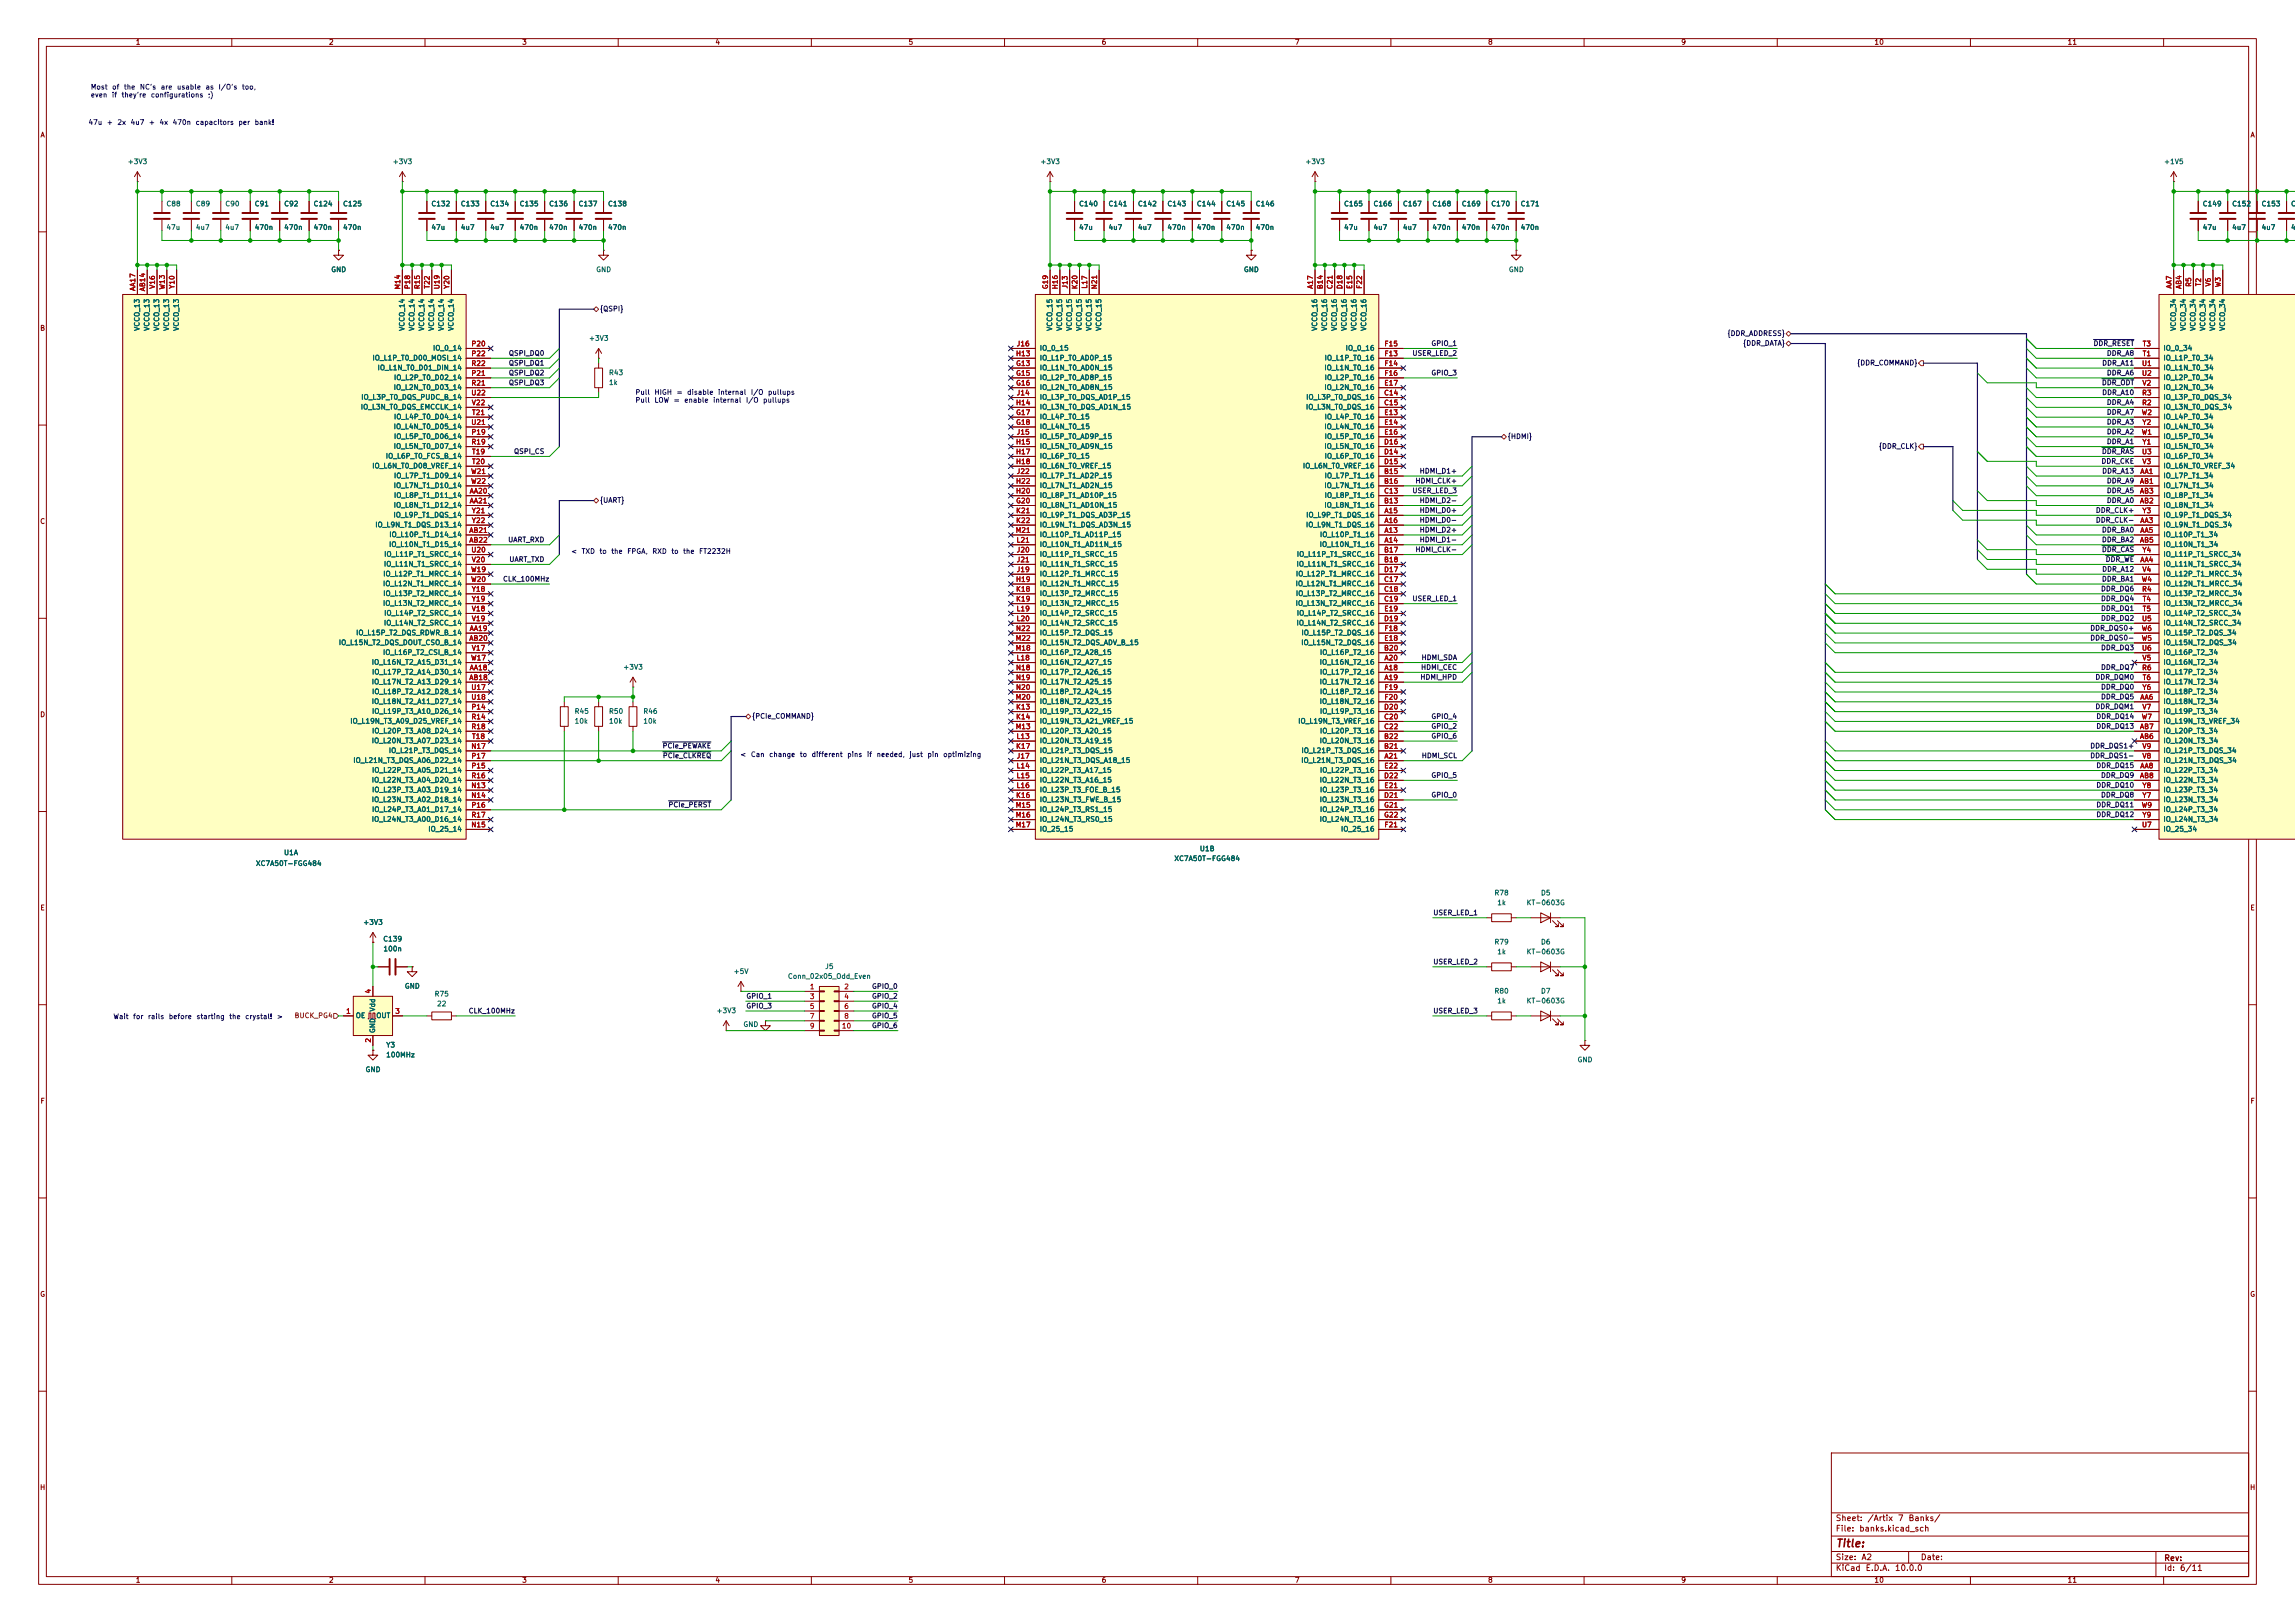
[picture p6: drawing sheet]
<svg xmlns="http://www.w3.org/2000/svg" width="594mm" height="420mm" viewBox="0 0 594 420" stroke-linecap="round" stroke-linejoin="round" font-family="sans-serif">
<defs><g id="words">
<text font-size="2" fill="#840000" x="475" y="400.9">Title:</text>
<g font-size="1.5" fill="#840000">
<text x="475" y="394">Sheet:</text>
<text x="483.2" y="394">/Artix</text>
<text x="491.1" y="394">7</text>
<text x="493.8" y="394">Banks/</text>
<text x="475" y="396.7">File:</text>
<text x="481.1" y="396.7">banks.kicad_sch</text>
<text x="475" y="406.9">KiCad</text>
<text x="475" y="404.1">Size:</text>
<text x="481.7" y="404.1">A2</text>
<text x="482.7" y="406.9">E.D.A.</text>
<text x="490.3" y="406.9">10.0.0</text>
<text x="497" y="404.1">Date:</text>
<text x="560" y="404.3">Rev:</text>
<text x="560" y="406.9">Id:</text>
<text x="564.1" y="406.9">6/11</text>
</g>
<g font-size="1.3" fill="#840000">
<text x="35" y="11.9">1</text>
<text x="85" y="11.9">2</text>
<text x="135" y="11.9">3</text>
<text x="185" y="11.9">4</text>
<text x="235" y="11.9">5</text>
<text x="285" y="11.9">6</text>
<text x="335" y="11.9">7</text>
<text x="385" y="11.9">8</text>
<text x="435" y="11.9">9</text>
<text x="485" y="11.9">10</text>
<text x="535" y="11.9">11</text>
<text x="10.3" y="35.9">A</text>
<text x="582.3" y="35.9">A</text>
<text x="10.3" y="85.9">B</text>
<text x="10.3" y="135.9">C</text>
<text x="10.3" y="185.9">D</text>
<text x="10.3" y="235.9">E</text>
<text x="582.3" y="235.9">E</text>
<text x="10.3" y="285.9">F</text>
<text x="582.3" y="285.9">F</text>
<text x="10.3" y="335.9">G</text>
<text x="582.3" y="335.9">G</text>
<text x="10.2" y="385.9">H</text>
<text x="582.2" y="385.9">H</text>
<text x="35" y="409.9">1</text>
<text x="85" y="409.9">2</text>
<text x="135" y="409.9">3</text>
<text x="185" y="409.9">4</text>
<text x="235" y="409.9">5</text>
<text x="285" y="409.9">6</text>
<text x="335" y="409.9">7</text>
<text x="385" y="409.9">8</text>
<text x="435" y="409.9">9</text>
<text x="485" y="409.9">10</text>
<text x="535" y="409.9">11</text>
</g>
<g font-size="1.3" fill="#0000c2">
<text x="23.4" y="23.5">Most</text>
<text x="28.9" y="23.5">of</text>
<text x="31.9" y="23.5">the</text>
<text x="36.1" y="23.5">NC's</text>
<text x="41.5" y="23.5">are</text>
<text x="45.7" y="23.5">usable</text>
<text x="53.1" y="23.5">as</text>
<text x="56.4" y="23.5">I/O's</text>
<text x="62.5" y="23.5">too,</text>
<text x="23.4" y="25.5">even</text>
<text x="28.8" y="25.5">if</text>
<text x="31.3" y="25.5">they're</text>
<text x="38.9" y="25.5">configurations</text>
<text x="53.7" y="25.5">;)</text>
<text x="22.8" y="32.6">47u</text>
<text x="27.5" y="32.6">+</text>
<text x="30.2" y="32.6">2x</text>
<text x="33.7" y="32.6">4u7</text>
<text x="38.4" y="32.6">+</text>
<text x="41.1" y="32.6">4x</text>
<text x="44.5" y="32.6">470n</text>
<text x="50.5" y="32.6">capacitors</text>
<text x="61.6" y="32.6">per</text>
<text x="65.8" y="32.6">bank!</text>
<text x="164.3" y="102.5">Pull</text>
<text x="164.3" y="104.5">Pull</text>
<text x="169.3" y="102.5">HIGH</text>
<text x="169.3" y="104.5">LOW</text>
<text x="174.2" y="104.5">=</text>
<text x="175" y="102.5">=</text>
<text x="177" y="104.5">enable</text>
<text x="177.7" y="102.5">disable</text>
<text x="184.4" y="104.5">internal</text>
<text x="185.7" y="102.5">internal</text>
<text x="192.9" y="104.5">I/O</text>
<text x="194.2" y="102.5">I/O</text>
<text x="197.4" y="104.5">pullups</text>
<text x="198.6" y="102.5">pullups</text>
<text x="147.7" y="143.6">&lt;</text>
<text x="150.4" y="143.6">TXD</text>
<text x="155" y="143.6">to</text>
<text x="158.1" y="143.6">the</text>
<text x="162.2" y="143.6">FPGA,</text>
<text x="168.7" y="143.6">RXD</text>
<text x="173.6" y="143.6">to</text>
<text x="176.7" y="143.6">the</text>
<text x="180.8" y="143.6">FT2232H</text>
<text x="191.5" y="196.2">&lt;</text>
<text x="194.2" y="196.2">Can</text>
<text x="198.9" y="196.2">change</text>
<text x="206.9" y="196.2">to</text>
<text x="209.9" y="196.2">different</text>
<text x="219.1" y="196.2">pins</text>
<text x="224.3" y="196.2">if</text>
<text x="226.8" y="196.2">needed,</text>
<text x="235.2" y="196.2">just</text>
<text x="239.9" y="196.2">pin</text>
<text x="244" y="196.2">optimizing</text>
<text x="29.2" y="264">Wait</text>
<text x="34.3" y="264">for</text>
<text x="38.2" y="264">rails</text>
<text x="43.6" y="264">before</text>
<text x="50.7" y="264">starting</text>
<text x="59.2" y="264">the</text>
<text x="63.3" y="264">crystal!</text>
<text x="71.5" y="264">&gt;</text>
</g>
<g font-size="1.3" fill="#006464">
<text x="32.9" y="42.8">+3V3</text>
<text x="101.5" y="42.8">+3V3</text>
<text x="269.1" y="42.8">+3V3</text>
<text x="337.7" y="42.8">+3V3</text>
<text x="560" y="42.8">+1V5</text>
<text x="42.9" y="53.7">C88</text>
<text x="50.6" y="53.7">C89</text>
<text x="58.2" y="53.7">C90</text>
<text x="65.8" y="53.7">C91</text>
<text x="73.4" y="53.7">C92</text>
<text x="81" y="53.7">C124</text>
<text x="88.7" y="53.7">C125</text>
<text x="111.5" y="53.7">C132</text>
<text x="119.1" y="53.7">C133</text>
<text x="126.8" y="53.7">C134</text>
<text x="134.4" y="53.7">C135</text>
<text x="142" y="53.7">C136</text>
<text x="149.6" y="53.7">C137</text>
<text x="157.2" y="53.7">C138</text>
<text x="279.2" y="53.7">C140</text>
<text x="286.8" y="53.7">C141</text>
<text x="294.4" y="53.7">C142</text>
<text x="302" y="53.7">C143</text>
<text x="309.6" y="53.7">C144</text>
<text x="317.3" y="53.7">C145</text>
<text x="324.9" y="53.7">C146</text>
<text x="347.7" y="53.7">C165</text>
<text x="355.4" y="53.7">C166</text>
<text x="363" y="53.7">C167</text>
<text x="370.6" y="53.7">C168</text>
<text x="378.2" y="53.7">C169</text>
<text x="385.8" y="53.7">C170</text>
<text x="393.5" y="53.7">C171</text>
<text x="570" y="53.7">C149</text>
<text x="577.6" y="53.7">C152</text>
<text x="585.2" y="53.7">C153</text>
<text x="592.8" y="53.7">C1</text>
<text x="42.9" y="59.8">47u</text>
<text x="50.6" y="59.8">4u7</text>
<text x="58.2" y="59.8">4u7</text>
<text x="65.8" y="59.8">470n</text>
<text x="73.4" y="59.8">470n</text>
<text x="81" y="59.8">470n</text>
<text x="88.7" y="59.8">470n</text>
<text x="111.5" y="59.8">47u</text>
<text x="119.1" y="59.8">4u7</text>
<text x="126.8" y="59.8">4u7</text>
<text x="134.4" y="59.8">470n</text>
<text x="142" y="59.8">470n</text>
<text x="149.6" y="59.8">470n</text>
<text x="157.2" y="59.8">470n</text>
<text x="279.2" y="59.8">47u</text>
<text x="286.8" y="59.8">4u7</text>
<text x="294.4" y="59.8">4u7</text>
<text x="302" y="59.8">470n</text>
<text x="309.6" y="59.8">470n</text>
<text x="317.3" y="59.8">470n</text>
<text x="324.9" y="59.8">470n</text>
<text x="347.7" y="59.8">47u</text>
<text x="355.4" y="59.8">4u7</text>
<text x="363" y="59.8">4u7</text>
<text x="370.6" y="59.8">470n</text>
<text x="378.2" y="59.8">470n</text>
<text x="385.8" y="59.8">470n</text>
<text x="393.5" y="59.8">470n</text>
<text x="570" y="59.8">47u</text>
<text x="577.6" y="59.8">4u7</text>
<text x="585.2" y="59.8">4u7</text>
<text x="592.8" y="59.8">47</text>
<text x="85.6" y="70.7">GND</text>
<text x="154.2" y="70.7">GND</text>
<text x="321.8" y="70.7">GND</text>
<text x="390.4" y="70.7">GND</text>
<text x="36.4" y="85.8" transform="rotate(-90 36.4 85.8)">VCCO_13</text>
<text x="39" y="85.8" transform="rotate(-90 39 85.8)">VCCO_13</text>
<text x="41.5" y="85.8" transform="rotate(-90 41.5 85.8)">VCCO_13</text>
<text x="44" y="85.8" transform="rotate(-90 44 85.8)">VCCO_13</text>
<text x="46.6" y="85.8" transform="rotate(-90 46.6 85.8)">VCCO_13</text>
<text x="105" y="85.8" transform="rotate(-90 105 85.8)">VCCO_14</text>
<text x="107.5" y="85.8" transform="rotate(-90 107.5 85.8)">VCCO_14</text>
<text x="110.1" y="85.8" transform="rotate(-90 110.1 85.8)">VCCO_14</text>
<text x="112.6" y="85.8" transform="rotate(-90 112.6 85.8)">VCCO_14</text>
<text x="115.2" y="85.8" transform="rotate(-90 115.2 85.8)">VCCO_14</text>
<text x="117.7" y="85.8" transform="rotate(-90 117.7 85.8)">VCCO_14</text>
<text x="152.3" y="88.5">+3V3</text>
<text x="272.6" y="85.8" transform="rotate(-90 272.6 85.8)">VCCO_15</text>
<text x="275.2" y="85.8" transform="rotate(-90 275.2 85.8)">VCCO_15</text>
<text x="277.7" y="85.8" transform="rotate(-90 277.7 85.8)">VCCO_15</text>
<text x="280.3" y="85.8" transform="rotate(-90 280.3 85.8)">VCCO_15</text>
<text x="282.8" y="85.8" transform="rotate(-90 282.8 85.8)">VCCO_15</text>
<text x="285.3" y="85.8" transform="rotate(-90 285.3 85.8)">VCCO_15</text>
<text x="341.2" y="85.8" transform="rotate(-90 341.2 85.8)">VCCO_16</text>
<text x="343.8" y="85.8" transform="rotate(-90 343.8 85.8)">VCCO_16</text>
<text x="346.3" y="85.8" transform="rotate(-90 346.3 85.8)">VCCO_16</text>
<text x="348.8" y="85.8" transform="rotate(-90 348.8 85.8)">VCCO_16</text>
<text x="351.4" y="85.8" transform="rotate(-90 351.4 85.8)">VCCO_16</text>
<text x="353.9" y="85.8" transform="rotate(-90 353.9 85.8)">VCCO_16</text>
<text x="563.5" y="85.8" transform="rotate(-90 563.5 85.8)">VCCO_34</text>
<text x="566" y="85.8" transform="rotate(-90 566 85.8)">VCCO_34</text>
<text x="568.6" y="85.8" transform="rotate(-90 568.6 85.8)">VCCO_34</text>
<text x="571.1" y="85.8" transform="rotate(-90 571.1 85.8)">VCCO_34</text>
<text x="573.6" y="85.8" transform="rotate(-90 573.6 85.8)">VCCO_34</text>
<text x="576.2" y="85.8" transform="rotate(-90 576.2 85.8)">VCCO_34</text>
<text x="96.3" y="93.6">IO_L1P_T0_D00_MOSI_14</text>
<text x="111.9" y="91">IO_0_14</text>
<text x="269" y="93.6">IO_L1P_T0_AD0P_15</text>
<text x="269" y="91">IO_0_15</text>
<text x="342.7" y="93.6">IO_L1P_T0_16</text>
<text x="348.2" y="91">IO_0_16</text>
<text x="559.8" y="93.6">IO_L1P_T0_34</text>
<text x="559.8" y="91">IO_0_34</text>
<text x="97.6" y="96.1">IO_L1N_T0_D01_DIN_14</text>
<text x="101.8" y="101.2">IO_L2N_T0_D03_14</text>
<text x="101.8" y="98.7">IO_L2P_T0_D02_14</text>
<text x="157.5" y="97.4">R43</text>
<text x="157.5" y="99.9">1k</text>
<text x="269" y="96.1">IO_L1N_T0_AD0N_15</text>
<text x="269" y="98.7">IO_L2P_T0_AD8P_15</text>
<text x="269" y="101.2">IO_L2N_T0_AD8N_15</text>
<text x="342.6" y="101.2">IO_L2N_T0_16</text>
<text x="342.6" y="96.1">IO_L1N_T0_16</text>
<text x="342.7" y="98.7">IO_L2P_T0_16</text>
<text x="559.8" y="96.1">IO_L1N_T0_34</text>
<text x="559.8" y="98.7">IO_L2P_T0_34</text>
<text x="559.8" y="101.2">IO_L2N_T0_34</text>
<text x="93.2" y="106.3">IO_L3N_T0_DQS_EMCCLK_14</text>
<text x="93.4" y="103.7">IO_L3P_T0_DQS_PUDC_B_14</text>
<text x="269" y="106.3">IO_L3N_T0_DQS_AD1N_15</text>
<text x="269" y="103.7">IO_L3P_T0_DQS_AD1P_15</text>
<text x="337.9" y="106.3">IO_L3N_T0_DQS_16</text>
<text x="337.9" y="103.7">IO_L3P_T0_DQS_16</text>
<text x="559.8" y="106.3">IO_L3N_T0_DQS_34</text>
<text x="559.8" y="103.7">IO_L3P_T0_DQS_34</text>
<text x="101.8" y="111.4">IO_L4N_T0_D05_14</text>
<text x="101.8" y="113.9">IO_L5P_T0_D06_14</text>
<text x="101.8" y="108.8">IO_L4P_T0_D04_14</text>
<text x="269" y="108.8">IO_L4P_T0_15</text>
<text x="269" y="111.4">IO_L4N_T0_15</text>
<text x="269" y="113.9">IO_L5P_T0_AD9P_15</text>
<text x="342.6" y="111.4">IO_L4N_T0_16</text>
<text x="342.7" y="108.8">IO_L4P_T0_16</text>
<text x="342.7" y="113.9">IO_L5P_T0_16</text>
<text x="559.8" y="113.9">IO_L5P_T0_34</text>
<text x="559.8" y="108.8">IO_L4P_T0_34</text>
<text x="559.8" y="111.4">IO_L4N_T0_34</text>
<text x="99.7" y="119">IO_L6P_T0_FCS_B_14</text>
<text x="101.8" y="116.4">IO_L5N_T0_D07_14</text>
<text x="269" y="116.4">IO_L5N_T0_AD9N_15</text>
<text x="269" y="119">IO_L6P_T0_15</text>
<text x="342.6" y="116.4">IO_L5N_T0_16</text>
<text x="342.7" y="119">IO_L6P_T0_16</text>
<text x="559.8" y="119">IO_L6P_T0_34</text>
<text x="559.8" y="116.4">IO_L5N_T0_34</text>
<text x="96.2" y="121.5">IO_L6N_T0_D08_VREF_14</text>
<text x="101.8" y="124.1">IO_L7P_T1_D09_14</text>
<text x="269" y="121.5">IO_L6N_T0_VREF_15</text>
<text x="269" y="124.1">IO_L7P_T1_AD2P_15</text>
<text x="337.1" y="121.5">IO_L6N_T0_VREF_16</text>
<text x="342.7" y="124.1">IO_L7P_T1_16</text>
<text x="559.8" y="124.1">IO_L7P_T1_34</text>
<text x="559.8" y="121.5">IO_L6N_T0_VREF_34</text>
<text x="101.8" y="131.7">IO_L8N_T1_D12_14</text>
<text x="101.8" y="126.6">IO_L7N_T1_D10_14</text>
<text x="101.8" y="129.1">IO_L8P_T1_D11_14</text>
<text x="269" y="131.7">IO_L8N_T1_AD10N_15</text>
<text x="269" y="129.1">IO_L8P_T1_AD10P_15</text>
<text x="269" y="126.6">IO_L7N_T1_AD2N_15</text>
<text x="342.6" y="131.7">IO_L8N_T1_16</text>
<text x="342.6" y="126.6">IO_L7N_T1_16</text>
<text x="342.7" y="129.1">IO_L8P_T1_16</text>
<text x="559.8" y="126.6">IO_L7N_T1_34</text>
<text x="559.8" y="131.7">IO_L8N_T1_34</text>
<text x="559.8" y="129.1">IO_L8P_T1_34</text>
<text x="97" y="136.8">IO_L9N_T1_DQS_D13_14</text>
<text x="101.7" y="134.2">IO_L9P_T1_DQS_14</text>
<text x="269" y="134.2">IO_L9P_T1_DQS_AD3P_15</text>
<text x="269" y="136.8">IO_L9N_T1_DQS_AD3N_15</text>
<text x="337.9" y="136.8">IO_L9N_T1_DQS_16</text>
<text x="337.9" y="134.2">IO_L9P_T1_DQS_16</text>
<text x="559.8" y="136.8">IO_L9N_T1_DQS_34</text>
<text x="559.8" y="134.2">IO_L9P_T1_DQS_34</text>
<text x="100.6" y="141.8">IO_L10N_T1_D15_14</text>
<text x="100.6" y="139.3">IO_L10P_T1_D14_14</text>
<text x="269" y="141.8">IO_L10N_T1_AD11N_15</text>
<text x="269" y="139.3">IO_L10P_T1_AD11P_15</text>
<text x="341.4" y="141.8">IO_L10N_T1_16</text>
<text x="341.5" y="139.3">IO_L10P_T1_16</text>
<text x="559.8" y="139.3">IO_L10P_T1_34</text>
<text x="559.8" y="141.8">IO_L10N_T1_34</text>
<text x="99.1" y="149.5">IO_L12P_T1_MRCC_14</text>
<text x="99.2" y="146.9">IO_L11N_T1_SRCC_14</text>
<text x="99.3" y="144.4">IO_L11P_T1_SRCC_14</text>
<text x="269" y="149.5">IO_L12P_T1_MRCC_15</text>
<text x="269" y="144.4">IO_L11P_T1_SRCC_15</text>
<text x="269" y="146.9">IO_L11N_T1_SRCC_15</text>
<text x="335.3" y="149.5">IO_L12P_T1_MRCC_16</text>
<text x="335.5" y="146.9">IO_L11N_T1_SRCC_16</text>
<text x="335.5" y="144.4">IO_L11P_T1_SRCC_16</text>
<text x="559.8" y="146.9">IO_L11N_T1_SRCC_34</text>
<text x="559.8" y="149.5">IO_L12P_T1_MRCC_34</text>
<text x="559.8" y="144.4">IO_L11P_T1_SRCC_34</text>
<text x="99" y="152">IO_L12N_T1_MRCC_14</text>
<text x="99.1" y="154.5">IO_L13P_T2_MRCC_14</text>
<text x="269" y="152">IO_L12N_T1_MRCC_15</text>
<text x="269" y="154.5">IO_L13P_T2_MRCC_15</text>
<text x="335.2" y="152">IO_L12N_T1_MRCC_16</text>
<text x="335.3" y="154.5">IO_L13P_T2_MRCC_16</text>
<text x="559.8" y="154.5">IO_L13P_T2_MRCC_34</text>
<text x="559.8" y="152">IO_L12N_T1_MRCC_34</text>
<text x="99" y="157.1">IO_L13N_T2_MRCC_14</text>
<text x="99.3" y="159.6">IO_L14P_T2_SRCC_14</text>
<text x="269" y="157.1">IO_L13N_T2_MRCC_15</text>
<text x="269" y="159.6">IO_L14P_T2_SRCC_15</text>
<text x="335.2" y="157.1">IO_L13N_T2_MRCC_16</text>
<text x="335.5" y="159.6">IO_L14P_T2_SRCC_16</text>
<text x="559.8" y="157.1">IO_L13N_T2_MRCC_34</text>
<text x="559.8" y="159.6">IO_L14P_T2_SRCC_34</text>
<text x="87.6" y="167.2">IO_L15N_T2_DQS_DOUT_CSO_B_14</text>
<text x="92" y="164.7">IO_L15P_T2_DQS_RDWR_B_14</text>
<text x="99.2" y="162.2">IO_L14N_T2_SRCC_14</text>
<text x="269" y="162.2">IO_L14N_T2_SRCC_15</text>
<text x="269" y="167.2">IO_L15N_T2_DQS_ADV_B_15</text>
<text x="269" y="164.7">IO_L15P_T2_DQS_15</text>
<text x="335.5" y="162.2">IO_L14N_T2_SRCC_16</text>
<text x="336.7" y="167.2">IO_L15N_T2_DQS_16</text>
<text x="336.7" y="164.7">IO_L15P_T2_DQS_16</text>
<text x="559.8" y="162.2">IO_L14N_T2_SRCC_34</text>
<text x="559.8" y="167.2">IO_L15N_T2_DQS_34</text>
<text x="559.8" y="164.7">IO_L15P_T2_DQS_34</text>
<text x="96.1" y="172.3">IO_L16N_T2_A15_D31_14</text>
<text x="99" y="169.8">IO_L16P_T2_CSI_B_14</text>
<text x="161.2" y="173.6">+3V3</text>
<text x="269" y="172.3">IO_L16N_T2_A27_15</text>
<text x="269" y="169.8">IO_L16P_T2_A28_15</text>
<text x="341.4" y="172.3">IO_L16N_T2_16</text>
<text x="341.5" y="169.8">IO_L16P_T2_16</text>
<text x="559.8" y="169.8">IO_L16P_T2_34</text>
<text x="559.8" y="172.3">IO_L16N_T2_34</text>
<text x="96.1" y="177.4">IO_L17N_T2_A13_D29_14</text>
<text x="96.1" y="174.9">IO_L17P_T2_A14_D30_14</text>
<text x="96.1" y="179.9">IO_L18P_T2_A12_D28_14</text>
<text x="269" y="174.9">IO_L17P_T2_A26_15</text>
<text x="269" y="177.4">IO_L17N_T2_A25_15</text>
<text x="269" y="179.9">IO_L18P_T2_A24_15</text>
<text x="341.4" y="177.4">IO_L17N_T2_16</text>
<text x="341.5" y="174.9">IO_L17P_T2_16</text>
<text x="341.5" y="179.9">IO_L18P_T2_16</text>
<text x="559.8" y="174.9">IO_L17P_T2_34</text>
<text x="559.8" y="177.4">IO_L17N_T2_34</text>
<text x="559.8" y="179.9">IO_L18P_T2_34</text>
<text x="96.1" y="182.5">IO_L18N_T2_A11_D27_14</text>
<text x="96.1" y="185">IO_L19P_T3_A10_D26_14</text>
<text x="148.6" y="185">R45</text>
<text x="157.5" y="185">R50</text>
<text x="166.4" y="185">R46</text>
<text x="269" y="185">IO_L19P_T3_A22_15</text>
<text x="269" y="182.5">IO_L18N_T2_A23_15</text>
<text x="341.4" y="182.5">IO_L18N_T2_16</text>
<text x="341.5" y="185">IO_L19P_T3_16</text>
<text x="559.8" y="182.5">IO_L18N_T2_34</text>
<text x="559.8" y="185">IO_L19P_T3_34</text>
<text x="90.5" y="187.6">IO_L19N_T3_A09_D25_VREF_14</text>
<text x="96.1" y="190.1">IO_L20P_T3_A08_D24_14</text>
<text x="148.6" y="187.6">10k</text>
<text x="157.5" y="187.6">10k</text>
<text x="166.4" y="187.6">10k</text>
<text x="269" y="187.6">IO_L19N_T3_A21_VREF_15</text>
<text x="269" y="190.1">IO_L20P_T3_A20_15</text>
<text x="335.9" y="187.6">IO_L19N_T3_VREF_16</text>
<text x="341.5" y="190.1">IO_L20P_T3_16</text>
<text x="559.8" y="190.1">IO_L20P_T3_34</text>
<text x="559.8" y="187.6">IO_L19N_T3_VREF_34</text>
<text x="91.3" y="197.7">IO_L21N_T3_DQS_A06_D22_14</text>
<text x="96.1" y="192.6">IO_L20N_T3_A07_D23_14</text>
<text x="100.5" y="195.2">IO_L21P_T3_DQS_14</text>
<text x="269" y="197.7">IO_L21N_T3_DQS_A18_15</text>
<text x="269" y="195.2">IO_L21P_T3_DQS_15</text>
<text x="269" y="192.6">IO_L20N_T3_A19_15</text>
<text x="336.7" y="197.7">IO_L21N_T3_DQS_16</text>
<text x="336.7" y="195.2">IO_L21P_T3_DQS_16</text>
<text x="341.4" y="192.6">IO_L20N_T3_16</text>
<text x="559.8" y="192.6">IO_L20N_T3_34</text>
<text x="559.8" y="197.7">IO_L21N_T3_DQS_34</text>
<text x="559.8" y="195.2">IO_L21P_T3_DQS_34</text>
<text x="96.1" y="202.8">IO_L22N_T3_A04_D20_14</text>
<text x="96.1" y="200.3">IO_L22P_T3_A05_D21_14</text>
<text x="269" y="200.3">IO_L22P_T3_A17_15</text>
<text x="269" y="202.8">IO_L22N_T3_A16_15</text>
<text x="341.4" y="202.8">IO_L22N_T3_16</text>
<text x="341.5" y="200.3">IO_L22P_T3_16</text>
<text x="559.8" y="200.3">IO_L22P_T3_34</text>
<text x="559.8" y="202.8">IO_L22N_T3_34</text>
<text x="96.1" y="207.9">IO_L23N_T3_A02_D18_14</text>
<text x="96.1" y="205.3">IO_L23P_T3_A03_D19_14</text>
<text x="269" y="207.9">IO_L23N_T3_FWE_B_15</text>
<text x="269" y="205.3">IO_L23P_T3_FOE_B_15</text>
<text x="341.4" y="207.9">IO_L23N_T3_16</text>
<text x="341.5" y="205.3">IO_L23P_T3_16</text>
<text x="559.8" y="207.9">IO_L23N_T3_34</text>
<text x="559.8" y="205.3">IO_L23P_T3_34</text>
<text x="96.1" y="213">IO_L24N_T3_A00_D16_14</text>
<text x="96.1" y="210.4">IO_L24P_T3_A01_D17_14</text>
<text x="110.7" y="215.5">IO_25_14</text>
<text x="269" y="210.4">IO_L24P_T3_RS1_15</text>
<text x="269" y="213">IO_L24N_T3_RS0_15</text>
<text x="269" y="215.5">IO_25_15</text>
<text x="341.4" y="213">IO_L24N_T3_16</text>
<text x="341.5" y="210.4">IO_L24P_T3_16</text>
<text x="346.9" y="215.5">IO_25_16</text>
<text x="559.8" y="215.5">IO_25_34</text>
<text x="559.8" y="210.4">IO_L24P_T3_34</text>
<text x="559.8" y="213">IO_L24N_T3_34</text>
<text x="73.4" y="221.6">U1A</text>
<text x="310.4" y="220.6">U1B</text>
<text x="66.1" y="224.4">XC7A50T-FGG484</text>
<text x="303.8" y="223.1">XC7A50T-FGG484</text>
<text x="386.7" y="232">R78</text>
<text x="398.7" y="232">D5</text>
<text x="93.9" y="239.6">+3V3</text>
<text x="387.4" y="234.5">1k</text>
<text x="395" y="234.5">KT-0603G</text>
<text x="99" y="243.9">C139</text>
<text x="386.7" y="244.7">R79</text>
<text x="398.7" y="244.7">D6</text>
<text x="99.1" y="246.5">100n</text>
<text x="213.4" y="251.1">J5</text>
<text x="387.4" y="247.2">1k</text>
<text x="395" y="247.2">KT-0603G</text>
<text x="104.6" y="256.1">GND</text>
<text x="189.7" y="252.3">+5V</text>
<text x="203.8" y="253.6">Conn_02x05_Odd_Even</text>
<text x="386.7" y="257.4">R80</text>
<text x="398.7" y="257.4">D7</text>
<text x="91.9" y="263.8">OE</text>
<text x="97.3" y="263.8">OUT</text>
<text x="97.4" y="261.9" transform="rotate(-90 97.4 261.9)">Vdd</text>
<text x="112.4" y="258.2">R75</text>
<text x="113" y="260.7">22</text>
<text x="185.3" y="262.5">+3V3</text>
<text x="387.4" y="259.9">1k</text>
<text x="395" y="259.9">KT-0603G</text>
<text x="97.4" y="267.5" transform="rotate(-90 97.4 267.5)">GND</text>
<text x="192.3" y="266">GND</text>
<text x="99.8" y="273.9">100MHz</text>
<text x="99.8" y="271.4">Y3</text>
<text x="408.2" y="275.2">GND</text>
<text x="94.5" y="277.7">GND</text>
</g>
<g font-size="1.3" fill="#a90000">
<text x="35.3" y="75.4" transform="rotate(-90 35.3 75.4)">AA17</text>
<text x="37.8" y="75.5" transform="rotate(-90 37.8 75.5)">AB14</text>
<text x="40.4" y="74.9" transform="rotate(-90 40.4 74.9)">V16</text>
<text x="42.9" y="75.1" transform="rotate(-90 42.9 75.1)">W13</text>
<text x="45.5" y="74.9" transform="rotate(-90 45.5 74.9)">Y10</text>
<text x="103.9" y="75.1" transform="rotate(-90 103.9 75.1)">M14</text>
<text x="106.4" y="75" transform="rotate(-90 106.4 75)">P18</text>
<text x="109" y="75" transform="rotate(-90 109 75)">R15</text>
<text x="111.5" y="74.8" transform="rotate(-90 111.5 74.8)">T22</text>
<text x="114" y="75" transform="rotate(-90 114 75)">U19</text>
<text x="116.6" y="74.9" transform="rotate(-90 116.6 74.9)">Y20</text>
<text x="271.5" y="75" transform="rotate(-90 271.5 75)">G19</text>
<text x="274.1" y="75" transform="rotate(-90 274.1 75)">H16</text>
<text x="276.6" y="74.8" transform="rotate(-90 276.6 74.8)">J13</text>
<text x="279.1" y="75" transform="rotate(-90 279.1 75)">K20</text>
<text x="281.7" y="74.9" transform="rotate(-90 281.7 74.9)">L17</text>
<text x="284.2" y="75" transform="rotate(-90 284.2 75)">N21</text>
<text x="340.1" y="74.9" transform="rotate(-90 340.1 74.9)">A17</text>
<text x="342.6" y="75" transform="rotate(-90 342.6 75)">B14</text>
<text x="345.2" y="75" transform="rotate(-90 345.2 75)">C21</text>
<text x="347.7" y="75" transform="rotate(-90 347.7 75)">D18</text>
<text x="350.3" y="74.9" transform="rotate(-90 350.3 74.9)">E15</text>
<text x="352.8" y="74.9" transform="rotate(-90 352.8 74.9)">F22</text>
<text x="562.4" y="74.8" transform="rotate(-90 562.4 74.8)">AA7</text>
<text x="564.9" y="74.9" transform="rotate(-90 564.9 74.9)">AB4</text>
<text x="567.4" y="74.4" transform="rotate(-90 567.4 74.4)">R5</text>
<text x="570" y="74.2" transform="rotate(-90 570 74.2)">T2</text>
<text x="572.5" y="74.3" transform="rotate(-90 572.5 74.3)">V6</text>
<text x="575.1" y="74.5" transform="rotate(-90 575.1 74.5)">W3</text>
<text x="121.9" y="89.9">P20</text>
<text x="263" y="89.9">J16</text>
<text x="358.2" y="89.9">F15</text>
<text x="554.4" y="89.9">T3</text>
<text x="121.9" y="92.5">P22</text>
<text x="121.9" y="95">R22</text>
<text x="262.8" y="92.5">H13</text>
<text x="262.8" y="95">G13</text>
<text x="358.2" y="92.5">F13</text>
<text x="358.2" y="95">F14</text>
<text x="554.3" y="95">U1</text>
<text x="554.4" y="92.5">T1</text>
<text x="121.9" y="97.5">P21</text>
<text x="121.9" y="100.1">R21</text>
<text x="262.8" y="97.5">G15</text>
<text x="262.8" y="100.1">G16</text>
<text x="358.2" y="100.1">E17</text>
<text x="358.2" y="97.5">F16</text>
<text x="554.3" y="97.5">U2</text>
<text x="554.4" y="100.1">V2</text>
<text x="121.8" y="102.6">U22</text>
<text x="122" y="105.2">V22</text>
<text x="122" y="107.7">T21</text>
<text x="262.8" y="105.2">H14</text>
<text x="262.8" y="107.7">G17</text>
<text x="263" y="102.6">J14</text>
<text x="358.1" y="102.6">C14</text>
<text x="358.1" y="105.2">C15</text>
<text x="358.2" y="107.7">E13</text>
<text x="554.2" y="107.7">W2</text>
<text x="554.3" y="105.2">R2</text>
<text x="554.3" y="102.6">R3</text>
<text x="121.8" y="110.2">U21</text>
<text x="121.9" y="112.8">P19</text>
<text x="262.8" y="110.2">G18</text>
<text x="263" y="112.8">J15</text>
<text x="358.2" y="110.2">E14</text>
<text x="358.2" y="112.8">E16</text>
<text x="554.2" y="112.8">W1</text>
<text x="554.4" y="110.2">Y2</text>
<text x="121.9" y="115.3">R19</text>
<text x="122" y="117.9">T19</text>
<text x="262.8" y="115.3">H15</text>
<text x="262.8" y="117.9">H17</text>
<text x="358.1" y="117.9">D14</text>
<text x="358.1" y="115.3">D16</text>
<text x="554.3" y="117.9">U3</text>
<text x="554.4" y="115.3">Y1</text>
<text x="121.8" y="122.9">W21</text>
<text x="121.8" y="125.5">W22</text>
<text x="122" y="120.4">T20</text>
<text x="262.8" y="120.4">H18</text>
<text x="262.8" y="125.5">H22</text>
<text x="263" y="122.9">J22</text>
<text x="358.1" y="122.9">B15</text>
<text x="358.1" y="125.5">B16</text>
<text x="358.1" y="120.4">D15</text>
<text x="553.7" y="125.5">AB1</text>
<text x="553.8" y="122.9">AA1</text>
<text x="554.4" y="120.4">V3</text>
<text x="121.4" y="128">AA20</text>
<text x="121.4" y="130.6">AA21</text>
<text x="262.8" y="128">H20</text>
<text x="262.8" y="130.6">G20</text>
<text x="358.1" y="130.6">B13</text>
<text x="358.1" y="128">C13</text>
<text x="553.7" y="130.6">AB2</text>
<text x="553.7" y="128">AB3</text>
<text x="122" y="133.1">Y21</text>
<text x="122" y="135.6">Y22</text>
<text x="262.8" y="133.1">K21</text>
<text x="262.8" y="135.6">K22</text>
<text x="358.2" y="133.1">A15</text>
<text x="358.2" y="135.6">A16</text>
<text x="553.8" y="135.6">AA3</text>
<text x="554.4" y="133.1">Y3</text>
<text x="121.3" y="138.2">AB21</text>
<text x="121.3" y="140.7">AB22</text>
<text x="121.8" y="143.3">U20</text>
<text x="262.8" y="138.2">M21</text>
<text x="263" y="140.7">L21</text>
<text x="263" y="143.3">J20</text>
<text x="358.1" y="143.3">B17</text>
<text x="358.2" y="138.2">A13</text>
<text x="358.2" y="140.7">A14</text>
<text x="553.7" y="140.7">AB5</text>
<text x="553.8" y="138.2">AA5</text>
<text x="554.4" y="143.3">Y4</text>
<text x="121.8" y="148.3">W19</text>
<text x="122" y="145.8">V20</text>
<text x="263" y="148.3">J19</text>
<text x="263" y="145.8">J21</text>
<text x="358.1" y="145.8">B18</text>
<text x="358.1" y="148.3">D17</text>
<text x="553.8" y="145.8">AA4</text>
<text x="554.4" y="148.3">V4</text>
<text x="121.8" y="150.9">W20</text>
<text x="122" y="153.4">Y18</text>
<text x="122" y="156">Y19</text>
<text x="262.8" y="150.9">H19</text>
<text x="262.8" y="153.4">K18</text>
<text x="262.8" y="156">K19</text>
<text x="358.1" y="150.9">C17</text>
<text x="358.1" y="153.4">C18</text>
<text x="358.1" y="156">C19</text>
<text x="554.2" y="150.9">W4</text>
<text x="554.3" y="153.4">R4</text>
<text x="554.4" y="156">T4</text>
<text x="122" y="158.5">V18</text>
<text x="122" y="161">V19</text>
<text x="263" y="158.5">L19</text>
<text x="263" y="161">L20</text>
<text x="358.1" y="161">D19</text>
<text x="358.2" y="158.5">E19</text>
<text x="554.3" y="161">U5</text>
<text x="554.4" y="158.5">T5</text>
<text x="121.3" y="166.1">AB20</text>
<text x="121.4" y="163.6">AA19</text>
<text x="262.8" y="166.1">M22</text>
<text x="262.8" y="163.6">N22</text>
<text x="358.2" y="166.1">E18</text>
<text x="358.2" y="163.6">F18</text>
<text x="554.2" y="166.1">W5</text>
<text x="554.2" y="163.6">W6</text>
<text x="121.4" y="173.7">AA18</text>
<text x="121.8" y="171.2">W17</text>
<text x="122" y="168.7">V17</text>
<text x="262.8" y="168.7">M18</text>
<text x="262.8" y="173.7">N18</text>
<text x="263" y="171.2">L18</text>
<text x="358.1" y="168.7">B20</text>
<text x="358.2" y="173.7">A18</text>
<text x="358.2" y="171.2">A20</text>
<text x="554.3" y="168.7">U6</text>
<text x="554.3" y="173.7">R6</text>
<text x="554.4" y="171.2">V5</text>
<text x="121.3" y="176.3">AB18</text>
<text x="121.8" y="178.8">U17</text>
<text x="262.8" y="176.3">N19</text>
<text x="262.8" y="178.8">N20</text>
<text x="358.2" y="176.3">A19</text>
<text x="358.2" y="178.8">F19</text>
<text x="554.4" y="178.8">Y6</text>
<text x="554.4" y="176.3">T6</text>
<text x="121.8" y="181.4">U18</text>
<text x="121.9" y="183.9">P14</text>
<text x="262.8" y="181.4">M20</text>
<text x="262.8" y="183.9">K13</text>
<text x="358.1" y="183.9">D20</text>
<text x="358.2" y="181.4">F20</text>
<text x="553.8" y="181.4">AA6</text>
<text x="554.4" y="183.9">V7</text>
<text x="121.9" y="186.4">R14</text>
<text x="121.9" y="189">R18</text>
<text x="122" y="191.5">T18</text>
<text x="262.8" y="189">M13</text>
<text x="262.8" y="186.4">K14</text>
<text x="263" y="191.5">L13</text>
<text x="358.1" y="191.5">B22</text>
<text x="358.1" y="186.4">C20</text>
<text x="358.1" y="189">C22</text>
<text x="553.7" y="191.5">AB6</text>
<text x="553.7" y="189">AB7</text>
<text x="554.2" y="186.4">W7</text>
<text x="121.8" y="194.1">N17</text>
<text x="121.9" y="196.6">P17</text>
<text x="262.8" y="194.1">K17</text>
<text x="263" y="196.6">J17</text>
<text x="358.1" y="194.1">B21</text>
<text x="358.2" y="196.6">A21</text>
<text x="554.4" y="196.6">V8</text>
<text x="554.4" y="194.1">V9</text>
<text x="121.9" y="199.1">P15</text>
<text x="121.9" y="201.7">R16</text>
<text x="263" y="199.1">L14</text>
<text x="263" y="201.7">L15</text>
<text x="358.1" y="201.7">D22</text>
<text x="358.2" y="199.1">E22</text>
<text x="553.7" y="201.7">AB8</text>
<text x="553.8" y="199.1">AA8</text>
<text x="121.8" y="204.2">N13</text>
<text x="121.8" y="206.8">N14</text>
<text x="121.9" y="209.3">P16</text>
<text x="262.8" y="209.3">M15</text>
<text x="262.8" y="206.8">K16</text>
<text x="263" y="204.2">L16</text>
<text x="358.1" y="206.8">D21</text>
<text x="358.1" y="209.3">G21</text>
<text x="358.2" y="204.2">E21</text>
<text x="554.2" y="209.3">W9</text>
<text x="554.4" y="206.8">Y7</text>
<text x="554.4" y="204.2">Y8</text>
<text x="121.8" y="214.4">N15</text>
<text x="121.9" y="211.8">R17</text>
<text x="262.8" y="211.8">M16</text>
<text x="262.8" y="214.4">M17</text>
<text x="358.1" y="211.8">G22</text>
<text x="358.2" y="214.4">F21</text>
<text x="554.3" y="214.4">U7</text>
<text x="554.4" y="211.8">Y9</text>
<text x="96.3" y="257.2" transform="rotate(-90 96.3 257.2)">4</text>
<text x="209.5" y="256.3">1</text>
<text x="218.4" y="256.3">2</text>
<text x="89.5" y="262.6">1</text>
<text x="102.2" y="262.6">3</text>
<text x="209.5" y="258.8">3</text>
<text x="209.5" y="261.4">5</text>
<text x="209.5" y="263.9">7</text>
<text x="218.4" y="258.8">4</text>
<text x="218.4" y="261.4">6</text>
<text x="218.4" y="263.9">8</text>
<text x="96.3" y="269.9" transform="rotate(-90 96.3 269.9)">2</text>
<text x="209.5" y="266.4">9</text>
<text x="217.8" y="266.4">10</text>
</g>
<g font-size="1.3" fill="#000084">
<text x="155.1" y="80.9">{QSPI}</text>
<text x="446.9" y="87.2">{DDR_ADDRESS}</text>
<text x="451" y="89.8">{DDR_DATA}</text>
<text x="480.5" y="94.8">{DDR_COMMAND}</text>
<text x="390.1" y="113.9">{HDMI}</text>
<text x="486.1" y="116.4">{DDR_CLK}</text>
<text x="155.1" y="130.4">{UART}</text>
<text x="194.5" y="186.3">{PCIe_COMMAND}</text>
</g>
<g font-size="1.3" fill="#0f0f0f">
<text x="370.3" y="89.8">GPIO_1</text>
<text x="541.7" y="89.8">DDR_RESET</text>
<text x="131.6" y="94.9">QSPI_DQ1</text>
<text x="131.6" y="92.4">QSPI_DQ0</text>
<text x="365.4" y="92.4">USER_LED_2</text>
<text x="544" y="94.9">DDR_A11</text>
<text x="545.2" y="92.4">DDR_A8</text>
<text x="131.6" y="97.4">QSPI_DQ2</text>
<text x="131.6" y="100">QSPI_DQ3</text>
<text x="370.3" y="97.4">GPIO_3</text>
<text x="543.9" y="100">DDR_ODT</text>
<text x="545.2" y="97.4">DDR_A6</text>
<text x="544" y="102.5">DDR_A10</text>
<text x="545.2" y="107.6">DDR_A7</text>
<text x="545.2" y="105.1">DDR_A4</text>
<text x="545.2" y="110.1">DDR_A3</text>
<text x="545.2" y="112.7">DDR_A2</text>
<text x="132.9" y="117.8">QSPI_CS</text>
<text x="543.9" y="117.8">DDR_RAS</text>
<text x="545.2" y="115.2">DDR_A1</text>
<text x="366.2" y="125.4">HDMI_CLK+</text>
<text x="367.3" y="122.8">HDMI_D1+</text>
<text x="543.8" y="120.3">DDR_CKE</text>
<text x="544" y="122.8">DDR_A13</text>
<text x="545.2" y="125.4">DDR_A9</text>
<text x="365.4" y="127.9">USER_LED_3</text>
<text x="367.3" y="130.5">HDMI_D2-</text>
<text x="545.2" y="130.5">DDR_A0</text>
<text x="545.2" y="127.9">DDR_A5</text>
<text x="367.3" y="135.5">HDMI_D0-</text>
<text x="367.3" y="133">HDMI_D0+</text>
<text x="542.3" y="133">DDR_CLK+</text>
<text x="542.3" y="135.5">DDR_CLK-</text>
<text x="131.4" y="140.6">UART_RXD</text>
<text x="366.2" y="143.2">HDMI_CLK-</text>
<text x="367.3" y="140.6">HDMI_D1-</text>
<text x="367.3" y="138.1">HDMI_D2+</text>
<text x="543.9" y="138.1">DDR_BA0</text>
<text x="543.9" y="143.2">DDR_CAS</text>
<text x="543.9" y="140.6">DDR_BA2</text>
<text x="131.7" y="145.7">UART_TXD</text>
<text x="544" y="148.2">DDR_A12</text>
<text x="544.9" y="145.7">DDR_WE</text>
<text x="130.1" y="150.8">CLK_100MHz</text>
<text x="365.4" y="155.9">USER_LED_1</text>
<text x="543.7" y="155.9">DDR_DQ4</text>
<text x="543.7" y="153.3">DDR_DQ6</text>
<text x="543.9" y="150.8">DDR_BA1</text>
<text x="543.7" y="160.9">DDR_DQ2</text>
<text x="543.7" y="158.4">DDR_DQ1</text>
<text x="540.9" y="166">DDR_DQS0-</text>
<text x="540.9" y="163.5">DDR_DQS0+</text>
<text x="367.7" y="173.6">HDMI_CEC</text>
<text x="367.8" y="171.1">HDMI_SDA</text>
<text x="543.7" y="173.6">DDR_DQ7</text>
<text x="543.7" y="168.6">DDR_DQ3</text>
<text x="367.5" y="176.2">HDMI_HPD</text>
<text x="542.2" y="176.2">DDR_DQM0</text>
<text x="543.7" y="178.7">DDR_DQ0</text>
<text x="542.2" y="183.8">DDR_DQM1</text>
<text x="543.7" y="181.3">DDR_DQ5</text>
<text x="370.3" y="186.3">GPIO_4</text>
<text x="370.3" y="191.4">GPIO_6</text>
<text x="370.3" y="188.9">GPIO_2</text>
<text x="542.4" y="186.3">DDR_DQ14</text>
<text x="542.4" y="188.9">DDR_DQ13</text>
<text x="171.4" y="194">PCIe_PEWAKE</text>
<text x="171.4" y="196.5">PCIe_CLKREQ</text>
<text x="367.9" y="196.5">HDMI_SCL</text>
<text x="540.9" y="194">DDR_DQS1+</text>
<text x="540.9" y="196.5">DDR_DQS1-</text>
<text x="370.3" y="201.6">GPIO_5</text>
<text x="542.4" y="199">DDR_DQ15</text>
<text x="543.7" y="201.6">DDR_DQ9</text>
<text x="172.9" y="209.2">PCIe_PERST</text>
<text x="370.3" y="206.7">GPIO_0</text>
<text x="542.4" y="209.2">DDR_DQ11</text>
<text x="542.4" y="204.1">DDR_DQ10</text>
<text x="543.7" y="206.7">DDR_DQ8</text>
<text x="542.4" y="211.7">DDR_DQ12</text>
<text x="370.8" y="237.1">USER_LED_1</text>
<text x="370.8" y="249.8">USER_LED_2</text>
<text x="225.6" y="256.2">GPIO_0</text>
<text x="121.2" y="262.5">CLK_100MHz</text>
<text x="193" y="258.7">GPIO_1</text>
<text x="193" y="261.3">GPIO_3</text>
<text x="225.6" y="261.3">GPIO_4</text>
<text x="225.6" y="258.7">GPIO_2</text>
<text x="225.6" y="263.8">GPIO_5</text>
<text x="370.8" y="262.5">USER_LED_3</text>
<text x="225.6" y="266.4">GPIO_6</text>
</g>
<text font-size="1.3" fill="#725600" x="76.1" y="263.8">BUCK_PG4</text>
</g></defs>
<g fill="none" stroke="#840000" stroke-width=".26">
<path d="M10 10h574v400h-574zM12 12h570v396h-570zM60 10v2M110 10v2M160 10v2M210 10v2M260 10v2M310 10v2M360 10v2M410 10v2M460 10v2M510 10v2"/>
<path d="M560 10v2M10 60h2M582 60h2M10 110h2M582 110h2M10 160h2M582 160h2M10 210h2M582 210h2M10 260h2M582 260h2M10 310h2"/>
<path d="M582 310h2M10 360h2M474 376h108v32h-108zM582 360h2M474 397.5h108M474 391.5h108M60 408v2M110 408v2M160 408v2M210 408v2M260 408v2M310 408v2"/>
<path d="M360 408v2M410 408v2M460 408v2M474 404.5h108M474 401.5h108M494 401.5v3M510 408v2M558 401.5v6.5M560 408v2"/>
</g>
<path d="M268 76.2h88.9v141h-88.9z" fill="#ffffc2"/>
<g fill="none" stroke="#840000" stroke-width=".26">
<path d="M268 76.2h88.9v141h-88.9zM271.8 69.9v6.3M274.3 69.9v6.3M276.9 69.9v6.3M279.4 69.9v6.3M281.9 69.9v6.3M284.5 69.9v6.3M340.4 69.9v6.3M342.9 69.9v6.3M345.4 69.9v6.3M348 69.9v6.3M350.5 69.9v6.3"/>
<path d="M353.1 69.9v6.3M261.6 92.7h6.4M261.6 95.3h6.4M261.6 90.2h6.4M261.6 97.8h6.4M356.9 92.7h6.3M356.9 95.3h6.3M356.9 90.2h6.3M356.9 97.8h6.3M261.6 102.9h6.4M261.6 105.4h6.4M261.6 118.1h6.4"/>
<path d="M261.6 115.6h6.4M261.6 108h6.4M261.6 110.5h6.4M261.6 113h6.4M261.6 100.3h6.4M356.9 102.9h6.3M356.9 105.4h6.3M356.9 118.1h6.3M356.9 115.6h6.3M356.9 108h6.3M356.9 110.5h6.3M356.9 113h6.3"/>
<path d="M356.9 100.3h6.3M261.6 138.4h6.4M261.6 133.4h6.4M261.6 135.9h6.4M261.6 130.8h6.4M261.6 123.2h6.4M261.6 125.7h6.4M261.6 128.3h6.4M261.6 120.7h6.4M356.9 138.4h6.3M356.9 133.4h6.3M356.9 135.9h6.3"/>
<path d="M356.9 130.8h6.3M356.9 123.2h6.3M356.9 125.7h6.3M356.9 128.3h6.3M356.9 120.7h6.3M261.6 141h6.4M261.6 143.5h6.4M261.6 146.1h6.4M261.6 151.1h6.4M261.6 153.7h6.4M261.6 156.2h6.4M261.6 148.6h6.4"/>
<path d="M261.6 158.8h6.4M356.9 141h6.3M356.9 143.5h6.3M356.9 146.1h6.3M356.9 151.1h6.3M356.9 153.7h6.3M356.9 156.2h6.3M356.9 148.6h6.3M356.9 158.8h6.3M261.6 174h6.4M261.6 176.5h6.4M261.6 171.5h6.4"/>
<path d="M261.6 168.9h6.4M261.6 161.3h6.4M261.6 166.4h6.4M261.6 163.8h6.4M261.6 179.1h6.4M356.9 174h6.3M356.9 176.5h6.3M356.9 171.5h6.3M356.9 168.9h6.3M356.9 161.3h6.3M356.9 166.4h6.3M356.9 163.8h6.3"/>
<path d="M356.9 179.1h6.3M145 182.9h2.1v5.1h-2.1zM146 181.6v1.3M146 188v1.2M261.6 196.9h6.4M261.6 194.3h6.4M261.6 191.8h6.4M261.6 186.7h6.4M261.6 189.2h6.4M261.6 184.2h6.4M261.6 199.4h6.4M261.6 181.6h6.4"/>
<path d="M356.9 196.9h6.3M356.9 194.3h6.3M356.9 191.8h6.3M356.9 186.7h6.3M356.9 189.2h6.3M356.9 184.2h6.3M356.9 199.4h6.3M356.9 181.6h6.3M261.6 207h6.4M261.6 201.9h6.4M261.6 204.5h6.4M261.6 214.6h6.4"/>
<path d="M261.6 209.6h6.4M261.6 212.1h6.4M356.9 207h6.3M356.9 201.9h6.3M356.9 204.5h6.3M356.9 214.6h6.3M356.9 209.6h6.3M356.9 212.1h6.3"/>
</g>
<path d="M31.7 76.2h88.9v141h-88.9z" fill="#ffffc2"/>
<g fill="none" stroke="#840000" stroke-width=".26">
<path d="M110.5 52.1v2.8M110.5 56.9v2.8M118.1 52.1v2.8M118.1 56.9v2.8M31.7 76.2h88.9v141h-88.9zM35.6 69.9v6.3M38.1 69.9v6.3M40.6 69.9v6.3M43.2 69.9v6.3M45.7 69.9v6.3M104.1 69.9v6.3M106.7 69.9v6.3"/>
<path d="M109.2 69.9v6.3M111.8 69.9v6.3M114.3 69.9v6.3M116.8 69.9v6.3M120.6 90.2h6.4M120.6 97.8h6.4M120.6 92.7h6.4M120.6 95.3h6.4M120.6 113h6.4M120.6 115.6h6.4M120.6 100.3h6.4M120.6 118.1h6.4"/>
<path d="M120.6 108h6.4M120.6 110.5h6.4M120.6 102.9h6.4M120.6 105.4h6.4M120.6 128.3h6.4M120.6 130.8h6.4M120.6 138.4h6.4M120.6 120.7h6.4M120.6 123.2h6.4M120.6 125.7h6.4M120.6 133.4h6.4M120.6 135.9h6.4"/>
<path d="M120.6 141h6.4M120.6 143.5h6.4M120.6 158.8h6.4M120.6 146.1h6.4M120.6 148.6h6.4M120.6 151.1h6.4M120.6 153.7h6.4M120.6 156.2h6.4M120.6 174h6.4M120.6 163.8h6.4M120.6 176.5h6.4M120.6 166.4h6.4"/>
<path d="M120.6 179.1h6.4M120.6 168.9h6.4M120.6 161.3h6.4M120.6 171.5h6.4M120.6 194.3h6.4M120.6 184.2h6.4M120.6 199.4h6.4M120.6 196.9h6.4M120.6 186.7h6.4M120.6 189.2h6.4M120.6 191.8h6.4M120.6 181.6h6.4"/>
<path d="M120.6 204.5h6.4M120.6 207h6.4M120.6 214.6h6.4M120.6 209.6h6.4M120.6 201.9h6.4M120.6 212.1h6.4M106.7 250.2v1.3h1.2l-1.2 1.2-1.3-1.2h1.3M106.7 250.2h.1M191.8 256.5h.1M191.8 254l-.8 1.3M191.8 254l.7 1.3M191.8 254v2.5"/>
<path d="M96.5 271.8v1.3h1.3l-1.3 1.2-1.3-1.2h1.3M96.5 271.8h.1M188 266.7h.1M188 264.2l-.8 1.2M188 264.2l.7 1.2M188 264.2v2.5M198.1 264.2v1.2h1.3l-1.3 1.3-1.3-1.3h1.3M198.1 264.2h.1"/>
</g>
<path d="M108.5 55.1h4M108.5 56.6h4M116.1 55.1h4M116.1 56.6h4" fill="none" stroke="#840000" stroke-width=".51"/>
<path d="M91.4 257.8h10.2v10.2h-10.2z" fill="#ffffc2"/>
<g fill="none" stroke="#840000" stroke-width=".26">
<path d="M141 52.1v2.8M141 56.9v2.8M316.2 52.1v2.8M316.2 56.9v2.8M354.3 52.1v2.8M354.3 56.9v2.8M361.9 52.1v2.8M361.9 56.9v2.8M369.6 52.1v2.8M369.6 56.9v2.8M377.2 52.1v2.8M377.2 56.9v2.8"/>
<path d="M392.4 52.1v2.8M392.4 56.9v2.8M562.6 47h.1M562.6 44.5l-.8 1.2M562.6 44.5l.8 1.2M562.6 44.5v2.5M569 52.1v2.8M569 56.9v2.8M576.6 52.1v2.8M576.6 56.9v2.8M584.2 52.1v2.8M584.2 56.9v2.8"/>
<path d="M591.8 52.1v2.8M591.8 56.9v2.8M154.9 92.7h.1M154.9 90.2l-.7 1.2M154.9 90.2l.8 1.2M154.9 90.2v2.5M153.9 182.9h2.1v5.1h-2.1zM154.9 181.6v1.3M154.9 188v1.2M162.8 182.9h2v5.1h-2zM163.8 181.6v1.3M163.8 188v1.2"/>
<path d="M91.4 257.8h10.2v10.2h-10.2zM96.5 243.8h.1M96.5 241.3v2.5M96.5 255.3v2.5M96.5 241.3l-.7 1.3M96.5 241.3l.8 1.3M97.8 250.2h2.8M102.6 250.2h2.8M88.9 262.9h2.5M95.2 263.7h.3v-1.6h.5v1.6h.5v-1.6h.5v1.6h.3M96.5 268v2.5M101.6 262.9h2.5"/>
<path d="M110.5 262.9h1.3M111.8 261.9h5v2h-5zM116.8 262.9h1.3"/>
</g>
<g fill="none" stroke="#840000" stroke-width=".51">
<path d="M138.9 55.1h4.1M138.9 56.6h4.1M314.2 55.1h4.1M314.2 56.6h4.1M352.3 55.1h4.1M352.3 56.6h4.1M359.9 55.1h4.1M359.9 56.6h4.1M367.5 55.1h4.1M367.5 56.6h4.1M375.2 55.1h4M375.2 56.6h4"/>
<path d="M390.4 55.1h4.1M390.4 56.6h4.1M566.9 55.1h4.1M566.9 56.6h4.1M574.5 55.1h4.1M574.5 56.6h4.1M582.2 55.1h4M582.2 56.6h4M589.8 55.1h4.1M589.8 56.6h4.1M100.8 248.2v4M102.4 248.2v4"/>
</g>
<path d="M212.1 255.3h5.1v12.7h-5.1z" fill="#ffffc2"/>
<g fill="none" stroke="#840000" stroke-width=".26">
<path d="M35.6 47h.1M35.6 44.5l-.8 1.2M35.6 44.5l.7 1.2M35.6 44.5v2.5M41.9 52.1v2.8M41.9 56.9v2.8M49.5 52.1v2.8M49.5 56.9v2.8M57.1 52.1v2.8M57.1 56.9v2.8M64.8 52.1v2.8M64.8 56.9v2.8"/>
<path d="M72.4 52.1v2.8M72.4 56.9v2.8M80 52.1v2.8M80 56.9v2.8M87.6 52.1v2.8M87.6 56.9v2.8M104.1 47h.1M104.1 44.5l-.7 1.2M104.1 44.5l.8 1.2M104.1 44.5v2.5M125.7 52.1v2.8M125.7 56.9v2.8"/>
<path d="M133.3 52.1v2.8M133.3 56.9v2.8M148.6 52.1v2.8M148.6 56.9v2.8M156.2 52.1v2.8M156.2 56.9v2.8M271.8 47h.1M271.8 44.5l-.8 1.2M271.8 44.5l.7 1.2M271.8 44.5v2.5M278.1 52.1v2.8M278.1 56.9v2.8"/>
<path d="M285.7 52.1v2.8M285.7 56.9v2.8M293.4 52.1v2.8M293.4 56.9v2.8M301 52.1v2.8M301 56.9v2.8M308.6 52.1v2.8M308.6 56.9v2.8M323.8 52.1v2.8M323.8 56.9v2.8M340.4 47h.1M340.4 44.5l-.8 1.2"/>
<path d="M340.4 44.5l.7 1.2M340.4 44.5v2.5M346.7 52.1v2.8M346.7 56.9v2.8M384.8 52.1v2.8M384.8 56.9v2.8M87.6 64.8v1.2h1.3l-1.3 1.3-1.2-1.3h1.2M87.6 64.8h.1M156.2 64.8v1.2h1.3l-1.3 1.3-1.3-1.3h1.3M156.2 64.8h.1M323.8 64.8v1.2h1.3l-1.3 1.3-1.2-1.3h1.2M323.8 64.8h.1"/>
<path d="M392.4 64.8v1.2h1.3l-1.3 1.3-1.2-1.3h1.2M392.4 64.8h.1M153.9 95.3h2.1v5h-2.1zM154.9 94v1.3M154.9 100.3v1.3M163.8 177.8h.1M163.8 175.3l-.7 1.2M163.8 175.3l.8 1.2M163.8 175.3v2.5M384.8 237.5h1.3M386.1 236.5h5.1v2h-5.1zM391.2 237.5h1.2"/>
<path d="M396.2 237.5h7.7M398.8 236.2l2.5 1.3-2.5 1.3zM401.3 236.2v2.6M401.8 238.3l1.6 1.5h-.8h.8v-.8M403.1 238.3l1.5 1.5h-.7h.7v-.8M208.3 256.5h3.8M208.3 259.1h3.8M212.1 255.3h5.1v12.7h-5.1zM212.1 256.4h1.3v.3h-1.3zM212.1 259h1.3v.2h-1.3zM215.9 256.4h1.3v.3h-1.3zM215.9 259h1.3v.2h-1.3z"/>
<path d="M217.2 256.5h3.8M217.2 259.1h3.8M384.8 250.2h1.3M386.1 249.2h5.1v2h-5.1zM391.2 250.2h1.2M396.2 250.2h7.7M398.8 248.9l2.5 1.3-2.5 1.3zM401.3 248.9v2.6M401.8 251l1.6 1.5h-.8h.8v-.8M403.1 251l1.5 1.5h-.7h.7v-.8M208.3 261.6h3.8M208.3 264.2h3.8"/>
<path d="M208.3 266.7h3.8M212.1 261.5h1.3v.2h-1.3zM212.1 264h1.3v.3h-1.3zM212.1 266.6h1.3v.2h-1.3zM215.9 261.5h1.3v.2h-1.3zM215.9 264h1.3v.3h-1.3zM215.9 266.6h1.3v.2h-1.3zM217.2 261.6h3.8M217.2 264.2h3.8M217.2 266.7h3.8M384.8 262.9h1.3M386.1 261.9h5.1v2h-5.1z"/>
<path d="M391.2 262.9h1.2M396.2 262.9h7.7M398.8 261.6l2.5 1.3-2.5 1.3zM401.3 261.6v2.6M401.8 263.7l1.6 1.5h-.8h.8v-.8M403.1 263.7l1.5 1.5h-.7h.7v-.8M410.2 269.2v1.3h1.3l-1.3 1.3-1.3-1.3h1.3M410.2 269.2h.1"/>
</g>
<g fill="none" stroke="#840000" stroke-width=".51">
<path d="M39.9 55.1h4M39.9 56.6h4M47.5 55.1h4.1M47.5 56.6h4.1M55.1 55.1h4.1M55.1 56.6h4.1M62.7 55.1h4.1M62.7 56.6h4.1M70.4 55.1h4M70.4 56.6h4M78 55.1h4M78 56.6h4"/>
<path d="M85.6 55.1h4.1M85.6 56.6h4.1M123.7 55.1h4.1M123.7 56.6h4.1M131.3 55.1h4.1M131.3 56.6h4.1M146.6 55.1h4M146.6 56.6h4M154.2 55.1h4M154.2 56.6h4M276.1 55.1h4.1M276.1 56.6h4.1"/>
<path d="M283.7 55.1h4.1M283.7 56.6h4.1M291.3 55.1h4.1M291.3 56.6h4.1M299 55.1h4M299 56.6h4M306.6 55.1h4M306.6 56.6h4M321.8 55.1h4.1M321.8 56.6h4.1M344.7 55.1h4M344.7 56.6h4"/>
<path d="M382.8 55.1h4M382.8 56.6h4"/>
</g>
<path d="M558.8 76.2h35.3v141h-35.3z" fill="#ffffc2"/>
<g fill="none" stroke="#840000" stroke-width=".26">
<path d="M64.8 52.1v2.8M64.8 56.9v2.8M72.4 52.1v2.8M72.4 56.9v2.8M80 52.1v2.8M80 56.9v2.8M87.6 52.1v2.8M87.6 56.9v2.8M110.5 52.1v2.8M110.5 56.9v2.8M118.1 52.1v2.8M118.1 56.9v2.8"/>
<path d="M125.7 52.1v2.8M125.7 56.9v2.8M133.3 52.1v2.8M133.3 56.9v2.8M141 52.1v2.8M141 56.9v2.8M148.6 52.1v2.8M148.6 56.9v2.8M156.2 52.1v2.8M156.2 56.9v2.8M278.1 52.1v2.8M278.1 56.9v2.8"/>
<path d="M285.7 52.1v2.8M285.7 56.9v2.8M293.4 52.1v2.8M293.4 56.9v2.8M301 52.1v2.8M301 56.9v2.8M308.6 52.1v2.8M308.6 56.9v2.8M316.2 52.1v2.8M316.2 56.9v2.8M323.8 52.1v2.8M323.8 56.9v2.8"/>
<path d="M346.7 52.1v2.8M346.7 56.9v2.8M354.3 52.1v2.8M354.3 56.9v2.8M361.9 52.1v2.8M361.9 56.9v2.8M369.6 52.1v2.8M369.6 56.9v2.8M377.2 52.1v2.8M377.2 56.9v2.8M384.8 52.1v2.8M384.8 56.9v2.8"/>
<path d="M392.4 52.1v2.8M392.4 56.9v2.8M569 52.1v2.8M569 56.9v2.8M576.6 52.1v2.8M576.6 56.9v2.8M584.2 52.1v2.8M584.2 56.9v2.8M591.8 52.1v2.8M591.8 56.9v2.8M35.6 69.9v6.3M38.1 69.9v6.3"/>
<path d="M40.6 69.9v6.3M43.2 69.9v6.3M45.7 69.9v6.3M87.6 64.8h.1M104.1 69.9v6.3M106.7 69.9v6.3M109.2 69.9v6.3M111.8 69.9v6.3M114.3 69.9v6.3M116.8 69.9v6.3M271.8 69.9v6.3M274.3 69.9v6.3"/>
<path d="M276.9 69.9v6.3M279.4 69.9v6.3M281.9 69.9v6.3M284.5 69.9v6.3M323.8 64.8h.1M340.4 69.9v6.3M342.9 69.9v6.3M345.4 69.9v6.3M348 69.9v6.3M350.5 69.9v6.3M353.1 69.9v6.3M562.6 69.9v6.3"/>
<path d="M565.1 69.9v6.3M567.7 69.9v6.3M570.2 69.9v6.3M572.8 69.9v6.3M575.3 69.9v6.3M594.1 76.2h-35.3v141h35.3M120.6 92.7h6.4M120.6 90.2h6.4M120.6 95.3h6.4M120.6 97.8h6.4M261.6 92.7h6.4M261.6 90.2h6.4"/>
<path d="M261.6 95.3h6.4M261.6 97.8h6.4M356.9 92.7h6.3M356.9 90.2h6.3M356.9 95.3h6.3M356.9 97.8h6.3M552.4 92.7h6.4M552.4 90.2h6.4M552.4 95.3h6.4M552.4 97.8h6.4M120.6 105.4h6.4M120.6 102.9h6.4"/>
<path d="M120.6 118.1h6.4M120.6 100.3h6.4M120.6 113h6.4M120.6 108h6.4M120.6 115.6h6.4M120.6 110.5h6.4M261.6 105.4h6.4M261.6 102.9h6.4M261.6 118.1h6.4M261.6 100.3h6.4M261.6 113h6.4M261.6 108h6.4"/>
<path d="M261.6 115.6h6.4M261.6 110.5h6.4M356.9 105.4h6.3M356.9 102.9h6.3M356.9 118.1h6.3M356.9 100.3h6.3M356.9 113h6.3M356.9 108h6.3M356.9 115.6h6.3M356.9 110.5h6.3M552.4 105.4h6.4M552.4 102.9h6.4"/>
<path d="M552.4 118.1h6.4M552.4 100.3h6.4M552.4 113h6.4M552.4 108h6.4M552.4 115.6h6.4M552.4 110.5h6.4M120.6 123.2h6.4M120.6 135.9h6.4M120.6 138.4h6.4M120.6 125.7h6.4M120.6 130.8h6.4M120.6 128.3h6.4"/>
<path d="M120.6 120.7h6.4M120.6 133.4h6.4M261.6 123.2h6.4M261.6 135.9h6.4M261.6 138.4h6.4M261.6 125.7h6.4M261.6 130.8h6.4M261.6 128.3h6.4M261.6 120.7h6.4M261.6 133.4h6.4M356.9 123.2h6.3M356.9 135.9h6.3"/>
<path d="M356.9 138.4h6.3M356.9 125.7h6.3M356.9 130.8h6.3M356.9 128.3h6.3M356.9 120.7h6.3M356.9 133.4h6.3M552.4 123.2h6.4M552.4 135.9h6.4M552.4 138.4h6.4M552.4 125.7h6.4M552.4 130.8h6.4M552.4 128.3h6.4"/>
<path d="M552.4 120.7h6.4M552.4 133.4h6.4M120.6 146.1h6.4M120.6 141h6.4M120.6 153.7h6.4M120.6 156.2h6.4M120.6 158.8h6.4M120.6 148.6h6.4M120.6 151.1h6.4M120.6 143.5h6.4M261.6 146.1h6.4M261.6 141h6.4"/>
<path d="M261.6 153.7h6.4M261.6 156.2h6.4M261.6 158.8h6.4M261.6 148.6h6.4M261.6 151.1h6.4M261.6 143.5h6.4M356.9 146.1h6.3M356.9 141h6.3M356.9 153.7h6.3M356.9 156.2h6.3M356.9 158.8h6.3M356.9 148.6h6.3"/>
<path d="M356.9 151.1h6.3M356.9 143.5h6.3M552.4 146.1h6.4M552.4 141h6.4M552.4 153.7h6.4M552.4 156.2h6.4M552.4 158.8h6.4M552.4 148.6h6.4M552.4 151.1h6.4M552.4 143.5h6.4M120.6 174h6.4M120.6 176.5h6.4"/>
<path d="M120.6 161.3h6.4M120.6 168.9h6.4M120.6 171.5h6.4M120.6 166.4h6.4M120.6 163.8h6.4M120.6 179.1h6.4M261.6 174h6.4M261.6 176.5h6.4M261.6 161.3h6.4M261.6 168.9h6.4M261.6 171.5h6.4M261.6 166.4h6.4"/>
<path d="M261.6 163.8h6.4M261.6 179.1h6.4M356.9 174h6.3M356.9 176.5h6.3M356.9 161.3h6.3M356.9 168.9h6.3M356.9 171.5h6.3M356.9 166.4h6.3M356.9 163.8h6.3M356.9 179.1h6.3M552.4 174h6.4M552.4 176.5h6.4"/>
<path d="M552.4 161.3h6.4M552.4 168.9h6.4M552.4 171.5h6.4M552.4 166.4h6.4M552.4 163.8h6.4M552.4 179.1h6.4M120.6 181.6h6.4M120.6 199.4h6.4M120.6 191.8h6.4M120.6 189.2h6.4M120.6 184.2h6.4M120.6 196.9h6.4"/>
<path d="M120.6 194.3h6.4M120.6 186.7h6.4M261.6 181.6h6.4M261.6 199.4h6.4M261.6 191.8h6.4M261.6 189.2h6.4M261.6 184.2h6.4M261.6 196.9h6.4M261.6 194.3h6.4M261.6 186.7h6.4M356.9 181.6h6.3M356.9 199.4h6.3"/>
<path d="M356.9 191.8h6.3M356.9 189.2h6.3M356.9 184.2h6.3M356.9 196.9h6.3M356.9 194.3h6.3M356.9 186.7h6.3M552.4 181.6h6.4M552.4 199.4h6.4M552.4 191.8h6.4M552.4 189.2h6.4M552.4 184.2h6.4M552.4 196.9h6.4"/>
<path d="M552.4 194.3h6.4M552.4 186.7h6.4M120.6 201.9h6.4M120.6 214.6h6.4M120.6 209.6h6.4M120.6 207h6.4M120.6 204.5h6.4M120.6 212.1h6.4M261.6 201.9h6.4M261.6 214.6h6.4M261.6 209.6h6.4M261.6 207h6.4"/>
<path d="M261.6 204.5h6.4M261.6 212.1h6.4M356.9 201.9h6.3M356.9 214.6h6.3M356.9 209.6h6.3M356.9 207h6.3M356.9 204.5h6.3M356.9 212.1h6.3M552.4 201.9h6.4M552.4 214.6h6.4M552.4 209.6h6.4M552.4 207h6.4"/>
<path d="M552.4 204.5h6.4M552.4 212.1h6.4M96.5 243.8h.1M96.5 255.3v2.5M97.8 250.2h2.8M102.6 250.2h2.8M106.7 250.2h.1M88.9 262.9h2.5M96.5 271.8h.1M96.5 268v2.5M101.6 262.9h2.5"/>
</g>
<path d="M153.7 80l.6-.6 .6 .6-.6 .6zM462.3 88.9l.6-.6 .6 .6-.6 .6zM462.3 86.4l.6-.7 .6 .7-.6 .6zM497.2 93.3h.6v1.3h-.6l-.6-.6zM388.6 113l.7-.6 .6 .6-.6 .7zM497.2 114.9h.6v1.3h-.6l-.6-.6zM153.7 129.5l.6-.6 .6 .6-.6 .7zM193 185.4l.7-.6 .6 .6-.6 .7zM86.4 262.3h.6l.6 .6-.6 .6h-.6z" fill="none" stroke="#725600" stroke-width=".26"/>
<path d="M541.9 87.9h10.4M544 98h8.3M544 115.8h8.3M544 141.2h8.3M545 143.7h7.3M171.5 192h12.5M171.6 194.5h12.4M173 207.2h11" fill="none" stroke="#0f0f0f" stroke-width=".26"/>
<path d="M153.7 80h-8.9v35.6M463.5 86.4h61v62.2M463.5 88.9h8.9v120.7M497.8 94h14v50.8M388.6 113h-7.6v81.3M497.8 115.6h7.7v16.5M153.7 129.5h-8.9v14M193 185.4h-3.8v21.6" fill="none" stroke="#000084" stroke-width=".3"/>
<g fill="none" stroke="#009600" stroke-width=".26">
<path d="M35.6 49.5h52v2.6M35.6 47v22.9M41.9 59.7v2.5h45.7M41.9 49.5v2.6M49.5 49.5v2.6M49.5 59.7v2.5M57.1 49.5v2.6M57.1 59.7v2.5M64.8 49.5v2.6M64.8 59.7v2.5M72.4 49.5v2.6M72.4 59.7v2.5"/>
<path d="M80 49.5v2.6M80 59.7v2.5M87.6 59.7v5.1M104.1 49.5h52.1v2.6M104.1 47v22.9M110.5 59.7v2.5h45.7M110.5 49.5v2.6M118.1 49.5v2.6M118.1 59.7v2.5M125.7 49.5v2.6M125.7 59.7v2.5M133.3 49.5v2.6"/>
<path d="M133.3 59.7v2.5M141 49.5v2.6M141 59.7v2.5M148.6 49.5v2.6M148.6 59.7v2.5M156.2 59.7v5.1M271.8 47v22.9M271.8 49.5h52v2.6M278.1 49.5v2.6M278.1 59.7v2.5h45.7M285.7 49.5v2.6M285.7 59.7v2.5"/>
<path d="M293.4 49.5v2.6M293.4 59.7v2.5M301 49.5v2.6M301 59.7v2.5M308.6 49.5v2.6M308.6 59.7v2.5M316.2 49.5v2.6M316.2 59.7v2.5M323.8 59.7v5.1M340.4 49.5h52v2.6M340.4 47v22.9M346.7 59.7v2.5h45.7"/>
<path d="M346.7 49.5v2.6M354.3 49.5v2.6M354.3 59.7v2.5M361.9 49.5v2.6M361.9 59.7v2.5M369.6 49.5v2.6M369.6 59.7v2.5M377.2 49.5v2.6M377.2 59.7v2.5M384.8 49.5v2.6M384.8 59.7v2.5M392.4 59.7v5.1"/>
<path d="M562.6 49.5h31.5M562.6 47v22.9M569 59.7v2.5h25.1M569 49.5v2.6M576.6 49.5v2.6M576.6 59.7v2.5M584.2 49.5v2.6M584.2 59.7v2.5M591.8 49.5v2.6M591.8 59.7v2.5M35.6 68.6h10.1v1.3M38.1 68.6v1.3"/>
<path d="M40.6 68.6v1.3M43.2 68.6v1.3M104.1 68.6h12.7v1.3M106.7 68.6v1.3M109.2 68.6v1.3M111.8 68.6v1.3M114.3 68.6v1.3M271.8 68.6h12.7v1.3M274.3 68.6v1.3M276.9 68.6v1.3M279.4 68.6v1.3M281.9 68.6v1.3"/>
<path d="M340.4 68.6h12.7v1.3M342.9 68.6v1.3M345.4 68.6v1.3M348 68.6v1.3M350.5 68.6v1.3M562.6 68.6h12.7v1.3M565.1 68.6v1.3M567.7 68.6v1.3M570.2 68.6v1.3M572.8 68.6v1.3M144.8 90.2l-2.6 2.5h-15.2M144.8 92.7l-2.6 2.6h-15.2"/>
<path d="M144.8 95.3l-2.6 2.5h-15.2M144.8 97.8l-2.6 2.5h-15.2M154.9 92.7v1.3M363.2 92.7h14M363.2 97.8h14M363.2 90.2h14M511.8 96.5l2.5 2.6h12.7v1.2h25.4M524.5 90.2l2.5 2.5h25.4M524.5 92.7l2.5 2.6h25.4M524.5 95.3l2.5 2.5h25.4M524.5 87.6l2.5 2.6h25.4M144.8 115.6l-2.6 2.5h-15.2"/>
<path d="M154.9 101.6v1.3h-27.9M511.8 116.8l2.5 2.6h12.7v1.3h25.4M524.5 115.6l2.5 2.5h25.4M524.5 100.3l2.5 2.6h25.4M524.5 113l2.5 2.6h25.4M524.5 108l2.5 2.5h25.4M524.5 110.5l2.5 2.5h25.4M524.5 105.4l2.5 2.6h25.4M524.5 102.9l2.5 2.5h25.4M144.8 138.4l-2.6 2.6h-15.2M363.2 128.3h14M381 135.9l-2.5 2.5h-15.3"/>
<path d="M381 130.8l-2.5 2.6h-15.3M381 138.4l-2.5 2.6h-15.3M381 133.4l-2.5 2.5h-15.3M381 123.2l-2.5 2.5h-15.3M381 128.3l-2.5 2.5h-15.3M381 120.7l-2.5 2.5h-15.3M505.5 129.5l2.5 2.6h19v1.3h25.4M505.5 132.1l2.5 2.5h19v1.3h25.4M511.8 127l2.5 2.5h12.7v1.3h25.4M511.8 139.7l2.5 2.5h12.7v1.3h25.4M524.5 135.9l2.5 2.5h25.4M524.5 138.4l2.5 2.6h25.4"/>
<path d="M524.5 123.2l2.5 2.5h25.4M524.5 125.7l2.5 2.6h25.4M524.5 120.7l2.5 2.5h25.4M127 151.1h15.2M144.8 143.5l-2.6 2.6h-15.2M363.2 156.2h14M381 141l-2.5 2.5h-15.3M472.4 151.1l2.6 2.6h77.4M472.4 158.8l2.6 2.5h77.4M472.4 153.7l2.6 2.5h77.4M472.4 156.2l2.6 2.6h77.4M511.8 142.2l2.5 2.6h12.7v1.3h25.4"/>
<path d="M511.8 144.8l2.5 2.5h12.7v1.3h25.4M524.5 148.6l2.5 2.5h25.4M163.8 177.8v3.8M381 171.5l-2.5 2.5h-15.3M381 168.9l-2.5 2.6h-15.3M381 174l-2.5 2.5h-15.3M472.4 171.5l2.6 2.5h77.4M472.4 174l2.6 2.5h77.4M472.4 163.8l2.6 2.6h77.4M472.4 161.3l2.6 2.5h77.4M472.4 176.5l2.6 2.6h77.4M472.4 179.1l2.6 2.5h77.4"/>
<path d="M472.4 166.4l2.6 2.5h77.4M146 189.2v20.4M154.9 180.3v1.3M154.9 189.2v7.7M163.8 180.3h-17.8v1.3M163.8 189.2v5.1M189.2 191.8l-2.5 2.5h-59.7M189.2 194.3l-2.5 2.6h-59.7M363.2 189.2h14M363.2 186.7h14M363.2 191.8h14M381 194.3l-2.5 2.6h-15.3"/>
<path d="M472.4 191.8l2.6 2.5h77.4M472.4 186.7l2.6 2.5h77.4M472.4 184.2l2.6 2.5h77.4M472.4 196.9l2.6 2.5h77.4M472.4 194.3l2.6 2.6h77.4M472.4 199.4l2.6 2.5h77.4M472.4 181.6l2.6 2.6h77.4M189.2 207l-2.5 2.6h-59.7M363.2 201.9h14M363.2 207h14M472.4 204.5l2.6 2.5h77.4M472.4 207l2.6 2.6h77.4"/>
<path d="M472.4 201.9l2.6 2.6h77.4M472.4 209.6l2.6 2.5h77.4M370.8 237.5h14M392.4 237.5h3.8M403.9 237.5h6.3v31.7M96.5 250.2h1.3M96.5 243.8v11.5M105.4 250.2h1.3M191.8 256.5h16.5M193 259.1h15.3M221 259.1h11.4M221 256.5h11.4"/>
<path d="M370.8 250.2h14M392.4 250.2h3.8M403.9 250.2h6.3M87.6 262.9h1.3M96.5 270.5v1.3M104.1 262.9h6.4M118.1 262.9h15.2M188 266.7h20.3M193 261.6h15.3M198.1 264.2h10.2M221 264.2h11.4M221 261.6h11.4"/>
<path d="M221 266.7h11.4M370.8 262.9h14M392.4 262.9h3.8M403.9 262.9h6.3"/>
</g>
<g fill="none" stroke="#000084" stroke-width=".26">
<path d="M126.4 89.6l1.2 1.2M127.6 89.6l-1.2 1.2M261 92.1l1.2 1.2M261 97.2l1.2 1.2M261 99.7l1.2 1.2M261 89.6l1.2 1.2M261 94.6l1.2 1.3M262.2 92.1l-1.2 1.2M262.2 97.2l-1.2 1.2M262.2 99.7l-1.2 1.2M262.2 89.6l-1.2 1.2M262.2 94.6l-1.2 1.3"/>
<path d="M362.6 94.6l1.2 1.3M362.6 99.7l1.2 1.2M363.8 94.6l-1.2 1.3M363.8 99.7l-1.2 1.2M126.4 109.9l1.2 1.2M126.4 112.4l1.2 1.2M126.4 107.3l1.2 1.3M126.4 104.8l1.2 1.2M126.4 115l1.2 1.2M127.6 109.9l-1.2 1.2M127.6 112.4l-1.2 1.2M127.6 107.3l-1.2 1.3"/>
<path d="M127.6 104.8l-1.2 1.2M127.6 115l-1.2 1.2M261 117.5l1.2 1.2M261 112.4l1.2 1.2M261 115l1.2 1.2M261 102.3l1.2 1.2M261 107.3l1.2 1.3M261 109.9l1.2 1.2M261 104.8l1.2 1.2M262.2 117.5l-1.2 1.2M262.2 112.4l-1.2 1.2M262.2 115l-1.2 1.2"/>
<path d="M262.2 102.3l-1.2 1.2M262.2 107.3l-1.2 1.3M262.2 109.9l-1.2 1.2M262.2 104.8l-1.2 1.2M362.6 104.8l1.2 1.2M362.6 102.3l1.2 1.2M362.6 107.3l1.2 1.3M362.6 112.4l1.2 1.2M362.6 117.5l1.2 1.2M362.6 109.9l1.2 1.2M362.6 115l1.2 1.2M363.8 104.8l-1.2 1.2"/>
<path d="M363.8 102.3l-1.2 1.2M363.8 107.3l-1.2 1.3M363.8 112.4l-1.2 1.2M363.8 117.5l-1.2 1.2M363.8 109.9l-1.2 1.2M363.8 115l-1.2 1.2M126.4 132.7l1.2 1.3M126.4 135.3l1.2 1.2M126.4 137.8l1.2 1.2M126.4 127.7l1.2 1.2M126.4 122.6l1.2 1.2M126.4 120l1.2 1.3"/>
<path d="M126.4 125.1l1.2 1.2M126.4 130.2l1.2 1.2M127.6 132.7l-1.2 1.3M127.6 135.3l-1.2 1.2M127.6 137.8l-1.2 1.2M127.6 127.7l-1.2 1.2M127.6 122.6l-1.2 1.2M127.6 120l-1.2 1.3M127.6 125.1l-1.2 1.2M127.6 130.2l-1.2 1.2M261 120l1.2 1.3M261 137.8l1.2 1.2"/>
<path d="M261 135.3l1.2 1.2M261 132.7l1.2 1.3M261 125.1l1.2 1.2M261 122.6l1.2 1.2M261 130.2l1.2 1.2M261 127.7l1.2 1.2M262.2 120l-1.2 1.3M262.2 137.8l-1.2 1.2M262.2 135.3l-1.2 1.2M262.2 132.7l-1.2 1.3M262.2 125.1l-1.2 1.2M262.2 122.6l-1.2 1.2"/>
<path d="M262.2 130.2l-1.2 1.2M262.2 127.7l-1.2 1.2M362.6 120l1.2 1.3M363.8 120l-1.2 1.3M126.4 142.9l1.2 1.2M126.4 153.1l1.2 1.2M126.4 155.6l1.2 1.2M126.4 158.1l1.2 1.3M126.4 148l1.2 1.2M127.6 142.9l-1.2 1.2M127.6 153.1l-1.2 1.2M127.6 155.6l-1.2 1.2"/>
<path d="M127.6 158.1l-1.2 1.3M127.6 148l-1.2 1.2M261 158.1l1.2 1.3M261 153.1l1.2 1.2M261 155.6l1.2 1.2M261 150.5l1.2 1.2M261 142.9l1.2 1.2M261 148l1.2 1.2M261 145.4l1.2 1.3M261 140.4l1.2 1.2M262.2 158.1l-1.2 1.3M262.2 153.1l-1.2 1.2"/>
<path d="M262.2 155.6l-1.2 1.2M262.2 150.5l-1.2 1.2M262.2 142.9l-1.2 1.2M262.2 148l-1.2 1.2M262.2 145.4l-1.2 1.3M262.2 140.4l-1.2 1.2M362.6 145.4l1.2 1.3M362.6 153.1l1.2 1.2M362.6 148l1.2 1.2M362.6 150.5l1.2 1.2M362.6 158.1l1.2 1.3M363.8 145.4l-1.2 1.3"/>
<path d="M363.8 153.1l-1.2 1.2M363.8 148l-1.2 1.2M363.8 150.5l-1.2 1.2M363.8 158.1l-1.2 1.3M126.4 175.9l1.2 1.2M126.4 178.5l1.2 1.2M126.4 170.8l1.2 1.3M126.4 173.4l1.2 1.2M126.4 168.3l1.2 1.2M126.4 165.8l1.2 1.2M126.4 163.2l1.2 1.2M126.4 160.7l1.2 1.2"/>
<path d="M127.6 175.9l-1.2 1.2M127.6 178.5l-1.2 1.2M127.6 170.8l-1.2 1.3M127.6 173.4l-1.2 1.2M127.6 168.3l-1.2 1.2M127.6 165.8l-1.2 1.2M127.6 163.2l-1.2 1.2M127.6 160.7l-1.2 1.2M261 168.3l1.2 1.2M261 163.2l1.2 1.2M261 160.7l1.2 1.2M261 178.5l1.2 1.2"/>
<path d="M261 173.4l1.2 1.2M261 175.9l1.2 1.2M261 170.8l1.2 1.3M261 165.8l1.2 1.2M262.2 168.3l-1.2 1.2M262.2 163.2l-1.2 1.2M262.2 160.7l-1.2 1.2M262.2 178.5l-1.2 1.2M262.2 173.4l-1.2 1.2M262.2 175.9l-1.2 1.2M262.2 170.8l-1.2 1.3M262.2 165.8l-1.2 1.2"/>
<path d="M362.6 160.7l1.2 1.2M362.6 163.2l1.2 1.2M362.6 165.8l1.2 1.2M362.6 178.5l1.2 1.2M362.6 168.3l1.2 1.2M363.8 160.7l-1.2 1.2M363.8 163.2l-1.2 1.2M363.8 165.8l-1.2 1.2M363.8 178.5l-1.2 1.2M363.8 168.3l-1.2 1.2M551.8 170.8l1.3 1.3M553.1 170.8l-1.3 1.3"/>
<path d="M126.4 191.2l1.2 1.2M126.4 188.6l1.2 1.2M126.4 181l1.2 1.2M126.4 198.8l1.2 1.2M126.4 183.5l1.2 1.3M126.4 186.1l1.2 1.2M127.6 191.2l-1.2 1.2M127.6 188.6l-1.2 1.2M127.6 181l-1.2 1.2M127.6 198.8l-1.2 1.2M127.6 183.5l-1.2 1.3M127.6 186.1l-1.2 1.2"/>
<path d="M261 181l1.2 1.2M261 183.5l1.2 1.3M261 196.2l1.2 1.3M261 188.6l1.2 1.2M261 193.7l1.2 1.2M261 191.2l1.2 1.2M261 186.1l1.2 1.2M261 198.8l1.2 1.2M262.2 181l-1.2 1.2M262.2 183.5l-1.2 1.3M262.2 196.2l-1.2 1.3M262.2 188.6l-1.2 1.2"/>
<path d="M262.2 193.7l-1.2 1.2M262.2 191.2l-1.2 1.2M262.2 186.1l-1.2 1.2M262.2 198.8l-1.2 1.2M362.6 193.7l1.2 1.2M362.6 183.5l1.2 1.3M362.6 181l1.2 1.2M362.6 198.8l1.2 1.2M363.8 193.7l-1.2 1.2M363.8 183.5l-1.2 1.3M363.8 181l-1.2 1.2M363.8 198.8l-1.2 1.2"/>
<path d="M551.8 191.2l1.3 1.2M553.1 191.2l-1.3 1.2M126.4 201.3l1.2 1.2M126.4 206.4l1.2 1.2M126.4 203.9l1.2 1.2M126.4 211.5l1.2 1.2M126.4 214l1.2 1.2M127.6 201.3l-1.2 1.2M127.6 206.4l-1.2 1.2M127.6 203.9l-1.2 1.2M127.6 211.5l-1.2 1.2M127.6 214l-1.2 1.2"/>
<path d="M261 201.3l1.2 1.2M261 208.9l1.2 1.3M261 214l1.2 1.2M261 211.5l1.2 1.2M261 206.4l1.2 1.2M261 203.9l1.2 1.2M262.2 201.3l-1.2 1.2M262.2 203.9l-1.2 1.2M262.2 208.9l-1.2 1.3M262.2 214l-1.2 1.2M262.2 211.5l-1.2 1.2M262.2 206.4l-1.2 1.2"/>
<path d="M362.6 211.5l1.2 1.2M362.6 214l1.2 1.2M362.6 208.9l1.2 1.3M362.6 203.9l1.2 1.2M363.8 211.5l-1.2 1.2M363.8 214l-1.2 1.2M363.8 208.9l-1.2 1.3M363.8 203.9l-1.2 1.2M551.8 214l1.3 1.2M553.1 214l-1.3 1.2"/>
</g>
<g fill="#009600" stroke="#009600" stroke-width=".26">
<circle cx="35.6" cy="49.5" r=".46"/>
<circle cx="64.8" cy="49.5" r=".46"/>
<circle cx="49.5" cy="49.5" r=".46"/>
<circle cx="57.1" cy="49.5" r=".46"/>
<circle cx="38.1" cy="68.6" r=".46"/>
<circle cx="40.6" cy="68.6" r=".46"/>
<circle cx="41.9" cy="49.5" r=".46"/>
<circle cx="35.6" cy="68.6" r=".46"/>
<circle cx="43.2" cy="68.6" r=".46"/>
<circle cx="57.1" cy="62.2" r=".46"/>
<circle cx="49.5" cy="62.2" r=".46"/>
<circle cx="163.8" cy="180.3" r=".46"/>
<circle cx="163.8" cy="194.3" r=".46"/>
<circle cx="154.9" cy="196.9" r=".46"/>
<circle cx="154.9" cy="180.3" r=".46"/>
<circle cx="146" cy="209.6" r=".46"/>
<circle cx="96.5" cy="250.2" r=".46"/>
<circle cx="118.1" cy="62.2" r=".46"/>
<circle cx="111.8" cy="68.6" r=".46"/>
<circle cx="114.3" cy="68.6" r=".46"/>
<circle cx="109.2" cy="68.6" r=".46"/>
<circle cx="72.4" cy="62.2" r=".46"/>
<circle cx="64.8" cy="62.2" r=".46"/>
<circle cx="87.6" cy="62.2" r=".46"/>
<circle cx="104.1" cy="68.6" r=".46"/>
<circle cx="106.7" cy="68.6" r=".46"/>
<circle cx="72.4" cy="49.5" r=".46"/>
<circle cx="80" cy="49.5" r=".46"/>
<circle cx="80" cy="62.2" r=".46"/>
<circle cx="104.1" cy="49.5" r=".46"/>
<circle cx="110.5" cy="49.5" r=".46"/>
<circle cx="350.5" cy="68.6" r=".46"/>
<circle cx="348" cy="68.6" r=".46"/>
<circle cx="340.4" cy="68.6" r=".46"/>
<circle cx="340.4" cy="49.5" r=".46"/>
<circle cx="323.8" cy="62.2" r=".46"/>
<circle cx="342.9" cy="68.6" r=".46"/>
<circle cx="345.4" cy="68.6" r=".46"/>
<circle cx="346.7" cy="49.5" r=".46"/>
<circle cx="354.3" cy="49.5" r=".46"/>
<circle cx="316.2" cy="49.5" r=".46"/>
<circle cx="377.2" cy="62.2" r=".46"/>
<circle cx="369.6" cy="62.2" r=".46"/>
<circle cx="354.3" cy="62.2" r=".46"/>
<circle cx="361.9" cy="62.2" r=".46"/>
<circle cx="369.6" cy="49.5" r=".46"/>
<circle cx="377.2" cy="49.5" r=".46"/>
<circle cx="361.9" cy="49.5" r=".46"/>
<circle cx="584.2" cy="62.2" r=".46"/>
<circle cx="576.6" cy="62.2" r=".46"/>
<circle cx="569" cy="49.5" r=".46"/>
<circle cx="576.6" cy="49.5" r=".46"/>
<circle cx="591.8" cy="62.2" r=".46"/>
<circle cx="570.2" cy="68.6" r=".46"/>
<circle cx="591.8" cy="49.5" r=".46"/>
<circle cx="584.2" cy="49.5" r=".46"/>
<circle cx="271.8" cy="68.6" r=".46"/>
<circle cx="276.9" cy="68.6" r=".46"/>
<circle cx="274.3" cy="68.6" r=".46"/>
<circle cx="279.4" cy="68.6" r=".46"/>
<circle cx="156.2" cy="62.2" r=".46"/>
<circle cx="148.6" cy="62.2" r=".46"/>
<circle cx="125.7" cy="49.5" r=".46"/>
<circle cx="118.1" cy="49.5" r=".46"/>
<circle cx="141" cy="49.5" r=".46"/>
<circle cx="133.3" cy="49.5" r=".46"/>
<circle cx="125.7" cy="62.2" r=".46"/>
<circle cx="133.3" cy="62.2" r=".46"/>
<circle cx="148.6" cy="49.5" r=".46"/>
<circle cx="141" cy="62.2" r=".46"/>
<circle cx="293.4" cy="62.2" r=".46"/>
<circle cx="281.9" cy="68.6" r=".46"/>
<circle cx="285.7" cy="49.5" r=".46"/>
<circle cx="285.7" cy="62.2" r=".46"/>
<circle cx="278.1" cy="49.5" r=".46"/>
<circle cx="271.8" cy="49.5" r=".46"/>
<circle cx="301" cy="62.2" r=".46"/>
<circle cx="308.6" cy="49.5" r=".46"/>
<circle cx="293.4" cy="49.5" r=".46"/>
<circle cx="301" cy="49.5" r=".46"/>
<circle cx="308.6" cy="62.2" r=".46"/>
<circle cx="316.2" cy="62.2" r=".46"/>
<circle cx="384.8" cy="62.2" r=".46"/>
<circle cx="384.8" cy="49.5" r=".46"/>
<circle cx="572.8" cy="68.6" r=".46"/>
<circle cx="567.7" cy="68.6" r=".46"/>
<circle cx="562.6" cy="68.6" r=".46"/>
<circle cx="565.1" cy="68.6" r=".46"/>
<circle cx="562.6" cy="49.5" r=".46"/>
<circle cx="392.4" cy="62.2" r=".46"/>
<circle cx="410.2" cy="250.2" r=".46"/>
<circle cx="410.2" cy="262.9" r=".46"/>
</g>
<use href="#words"/>
</svg>
